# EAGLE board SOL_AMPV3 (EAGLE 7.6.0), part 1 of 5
S_REV: 1.2

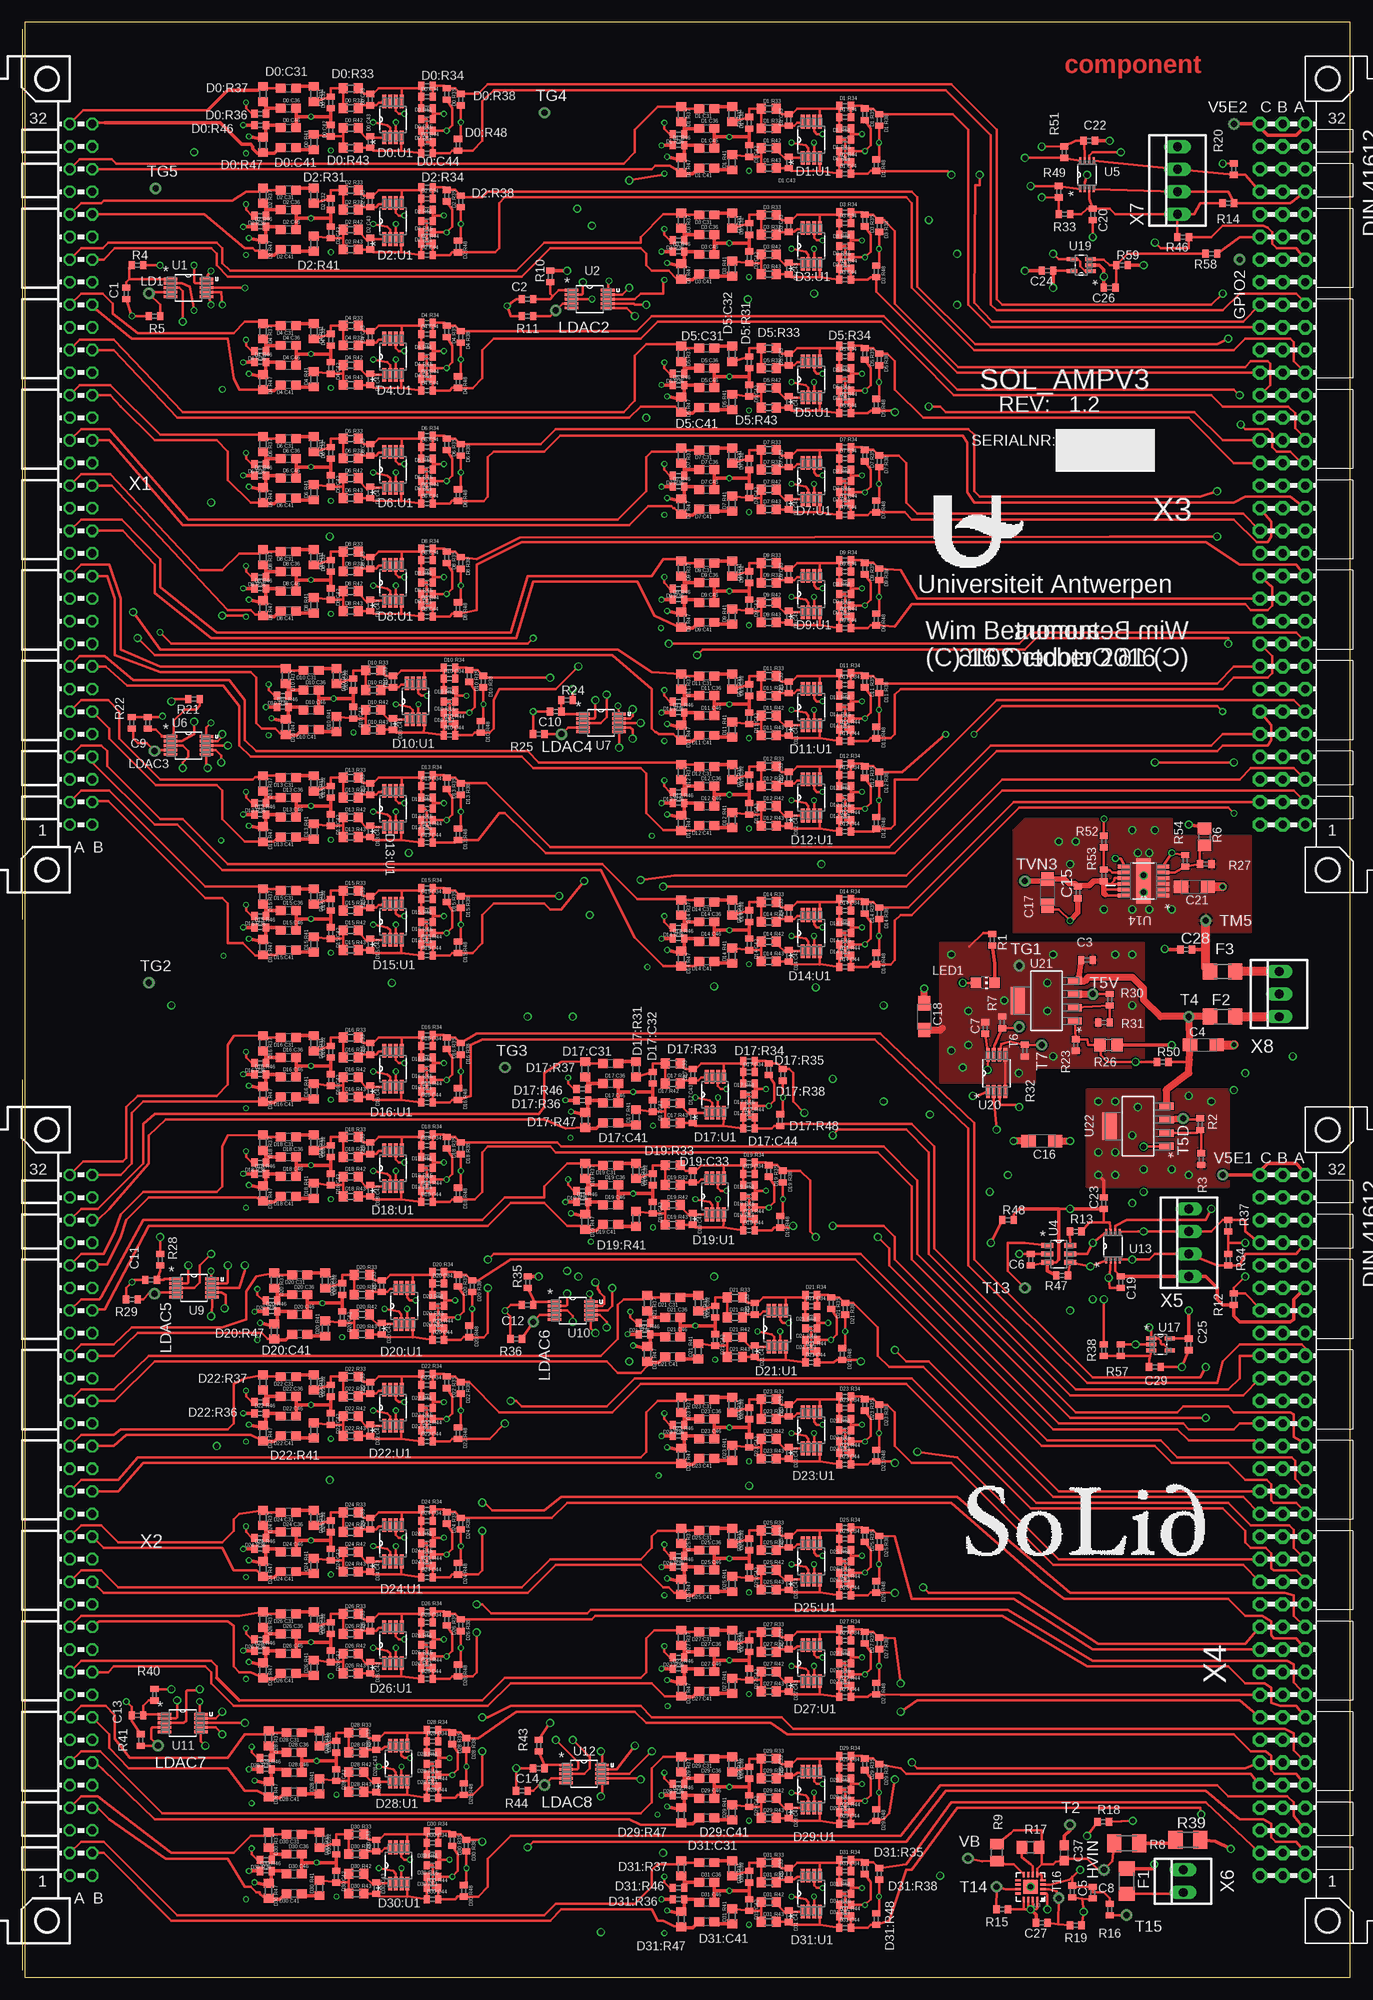
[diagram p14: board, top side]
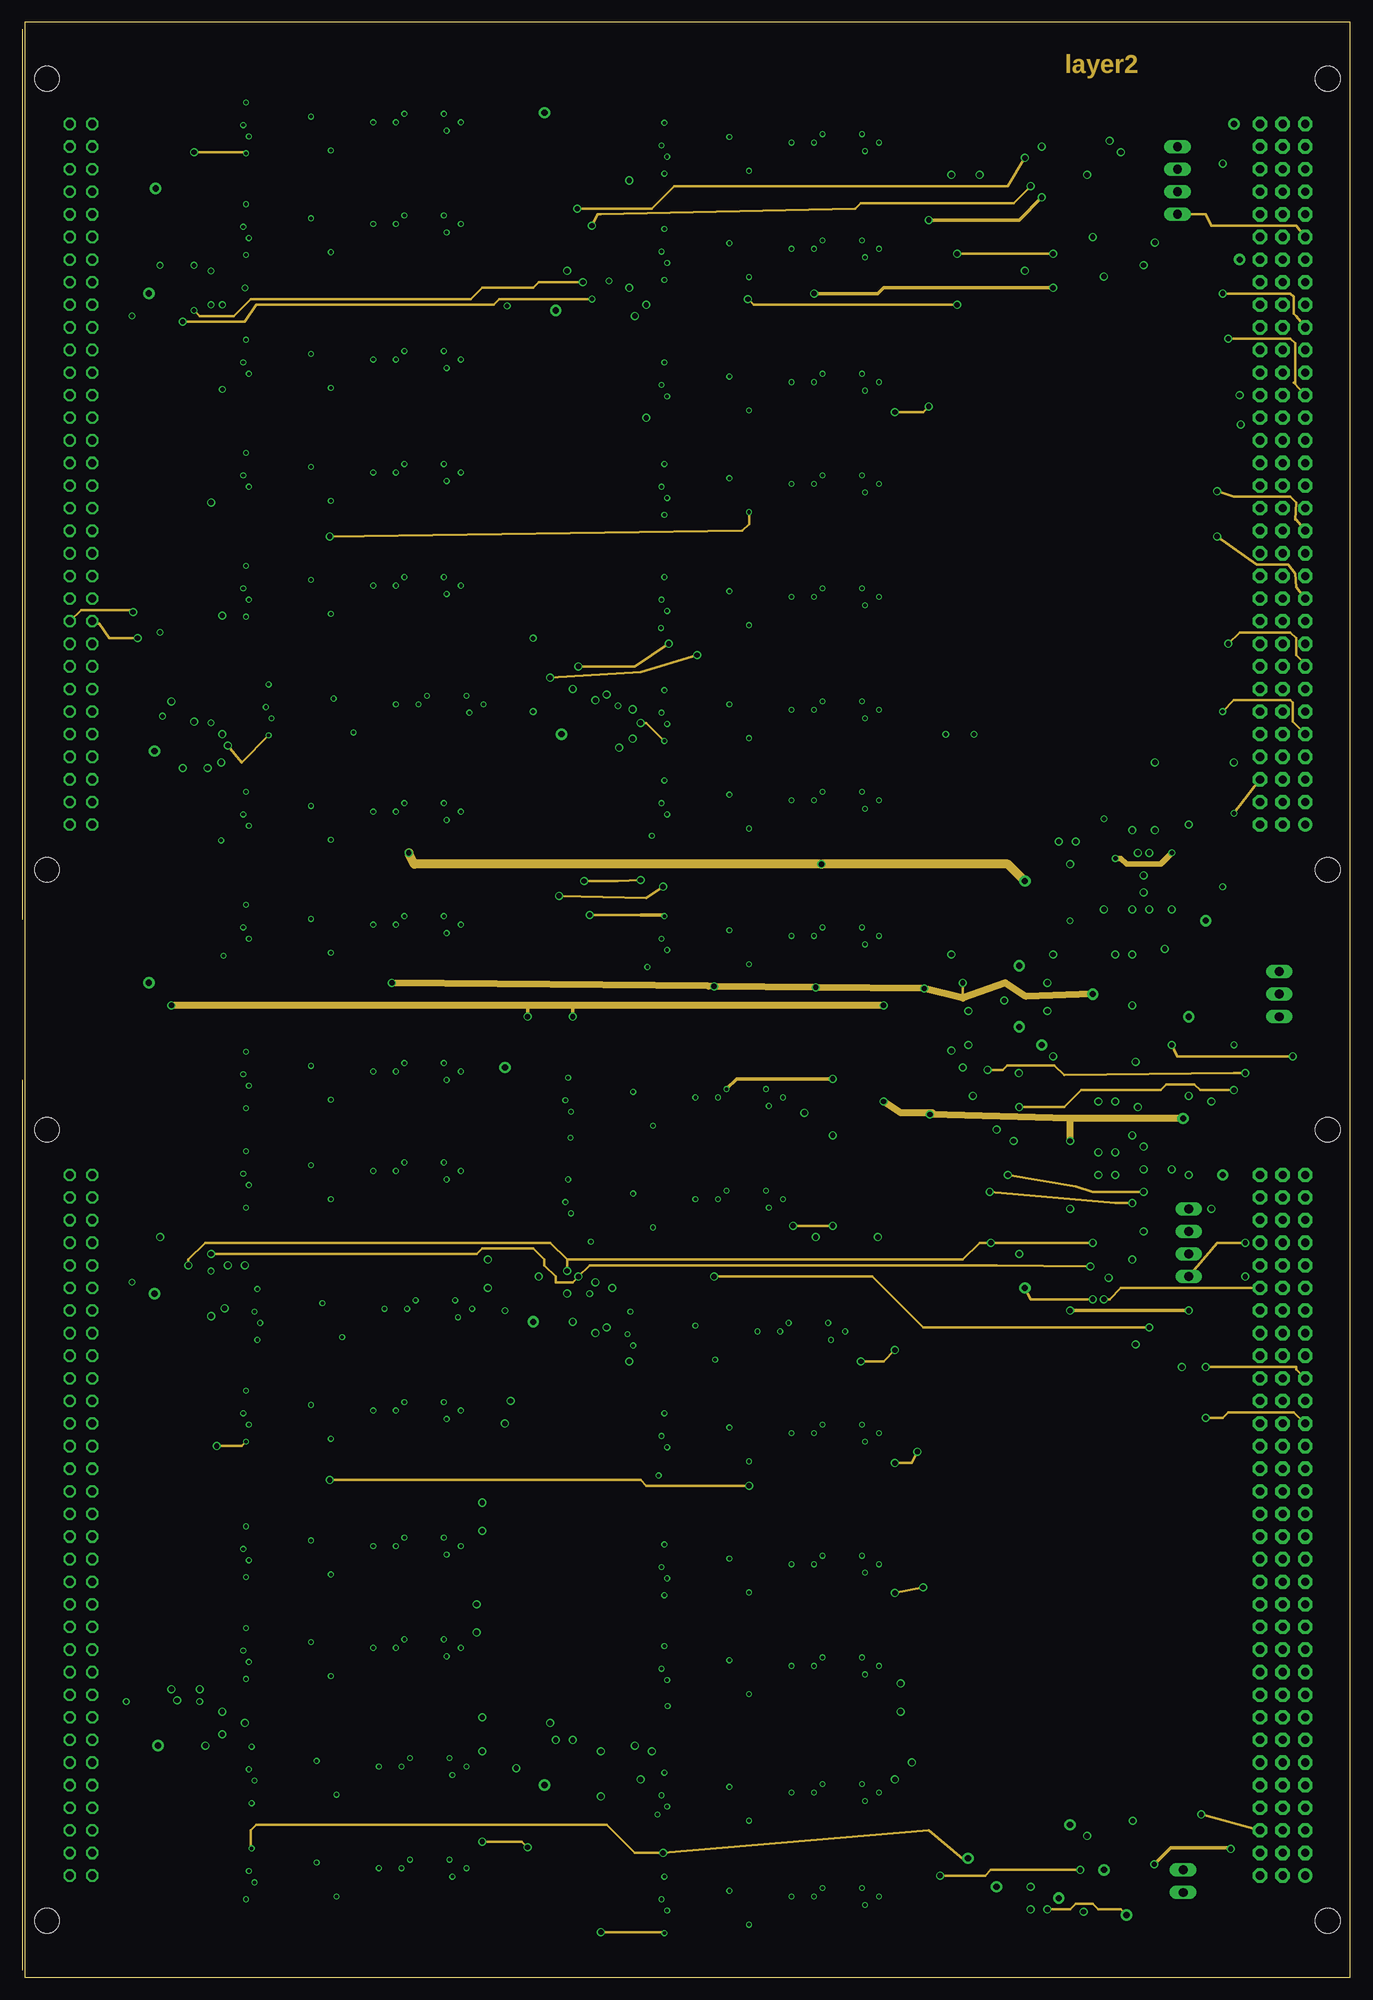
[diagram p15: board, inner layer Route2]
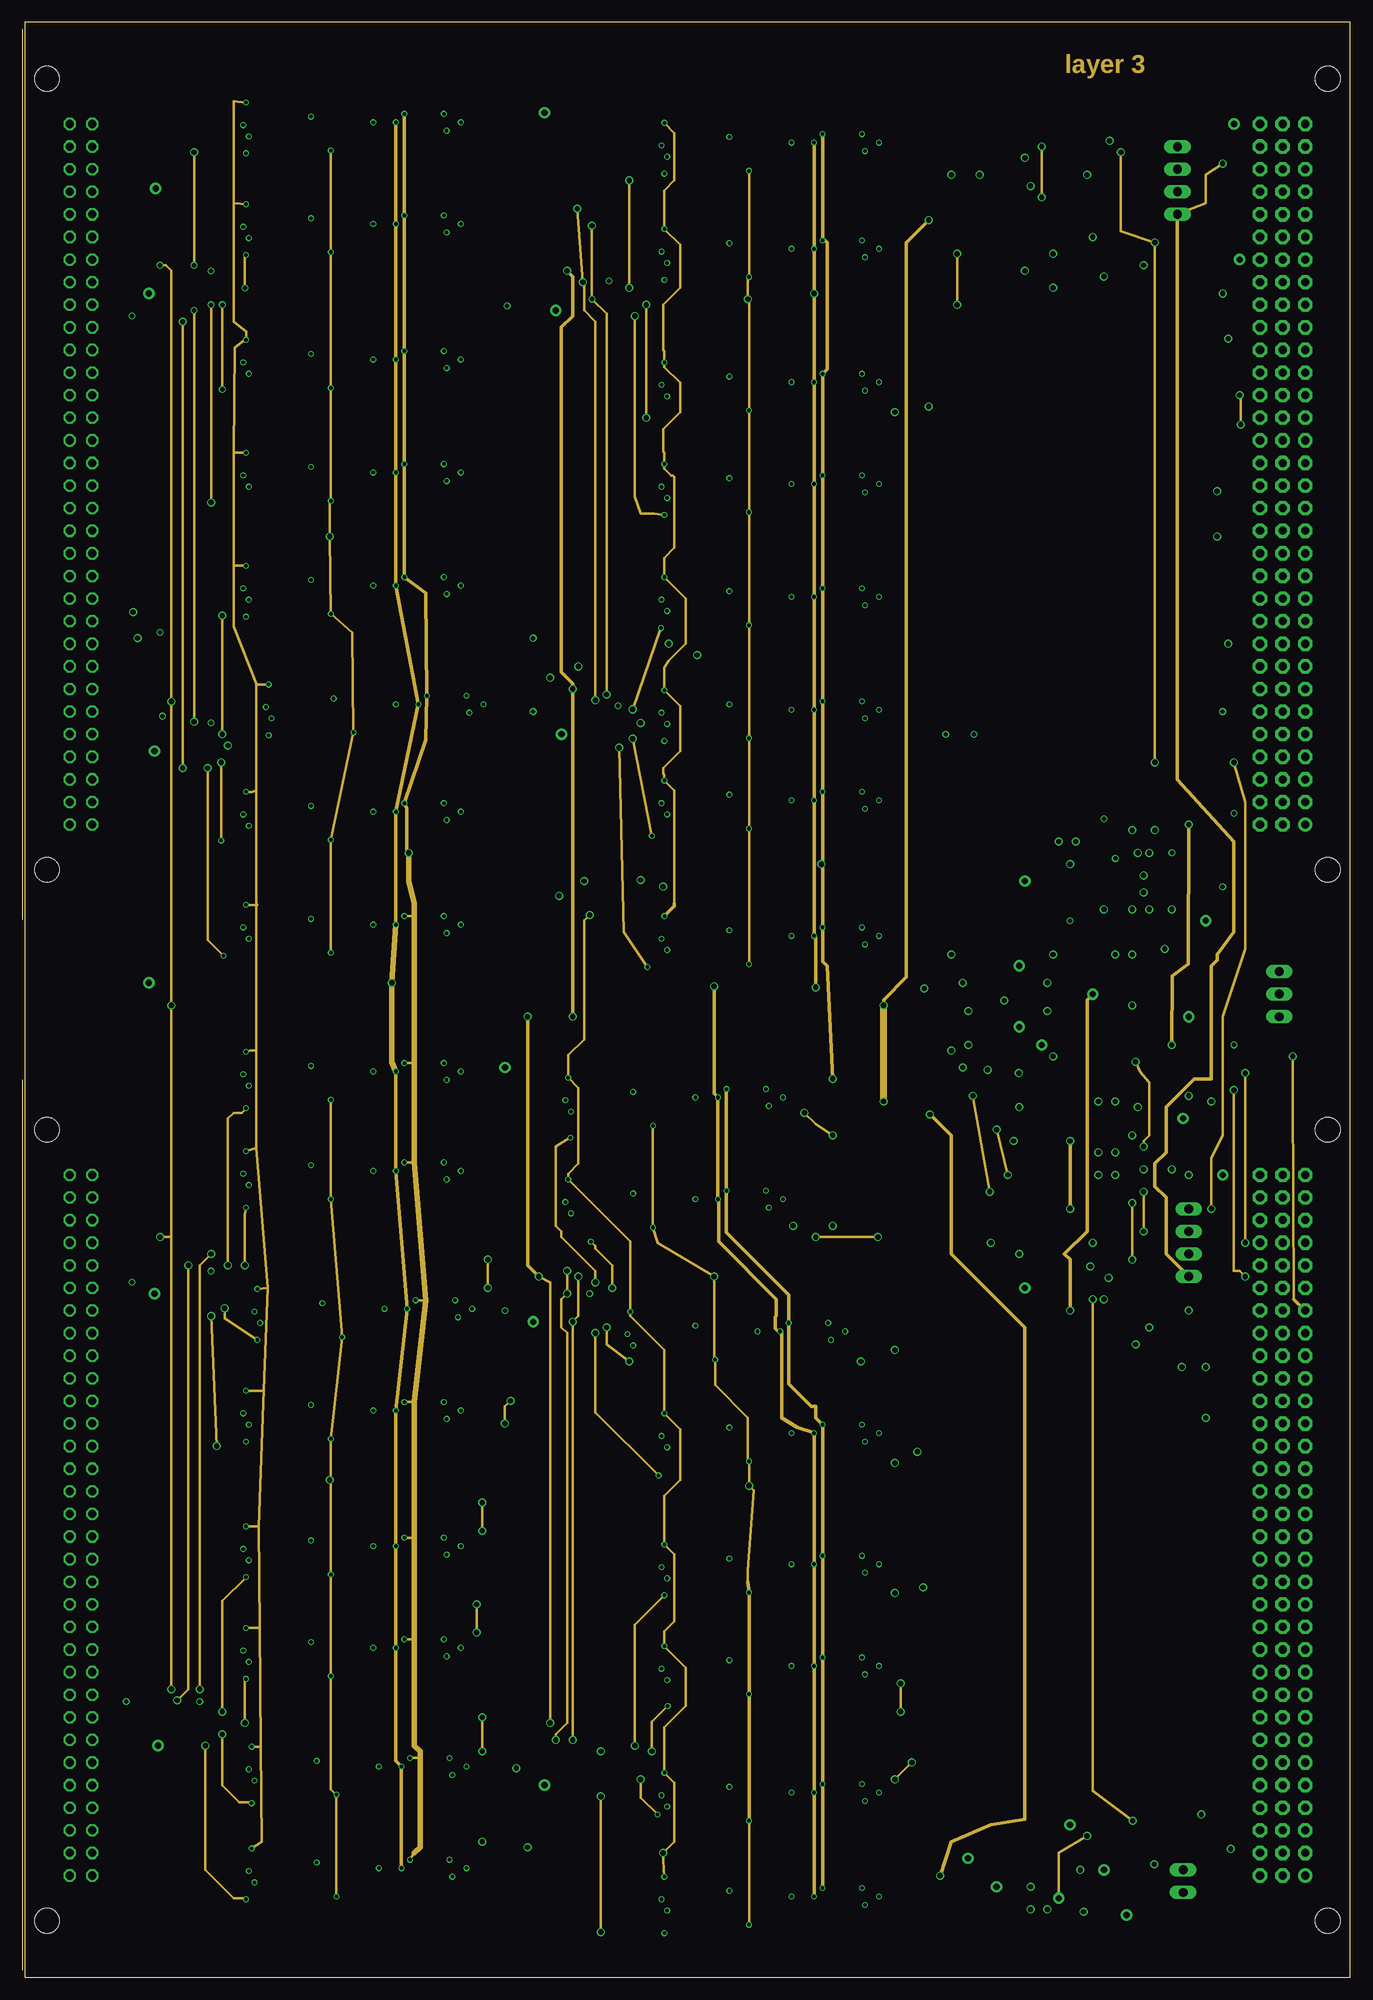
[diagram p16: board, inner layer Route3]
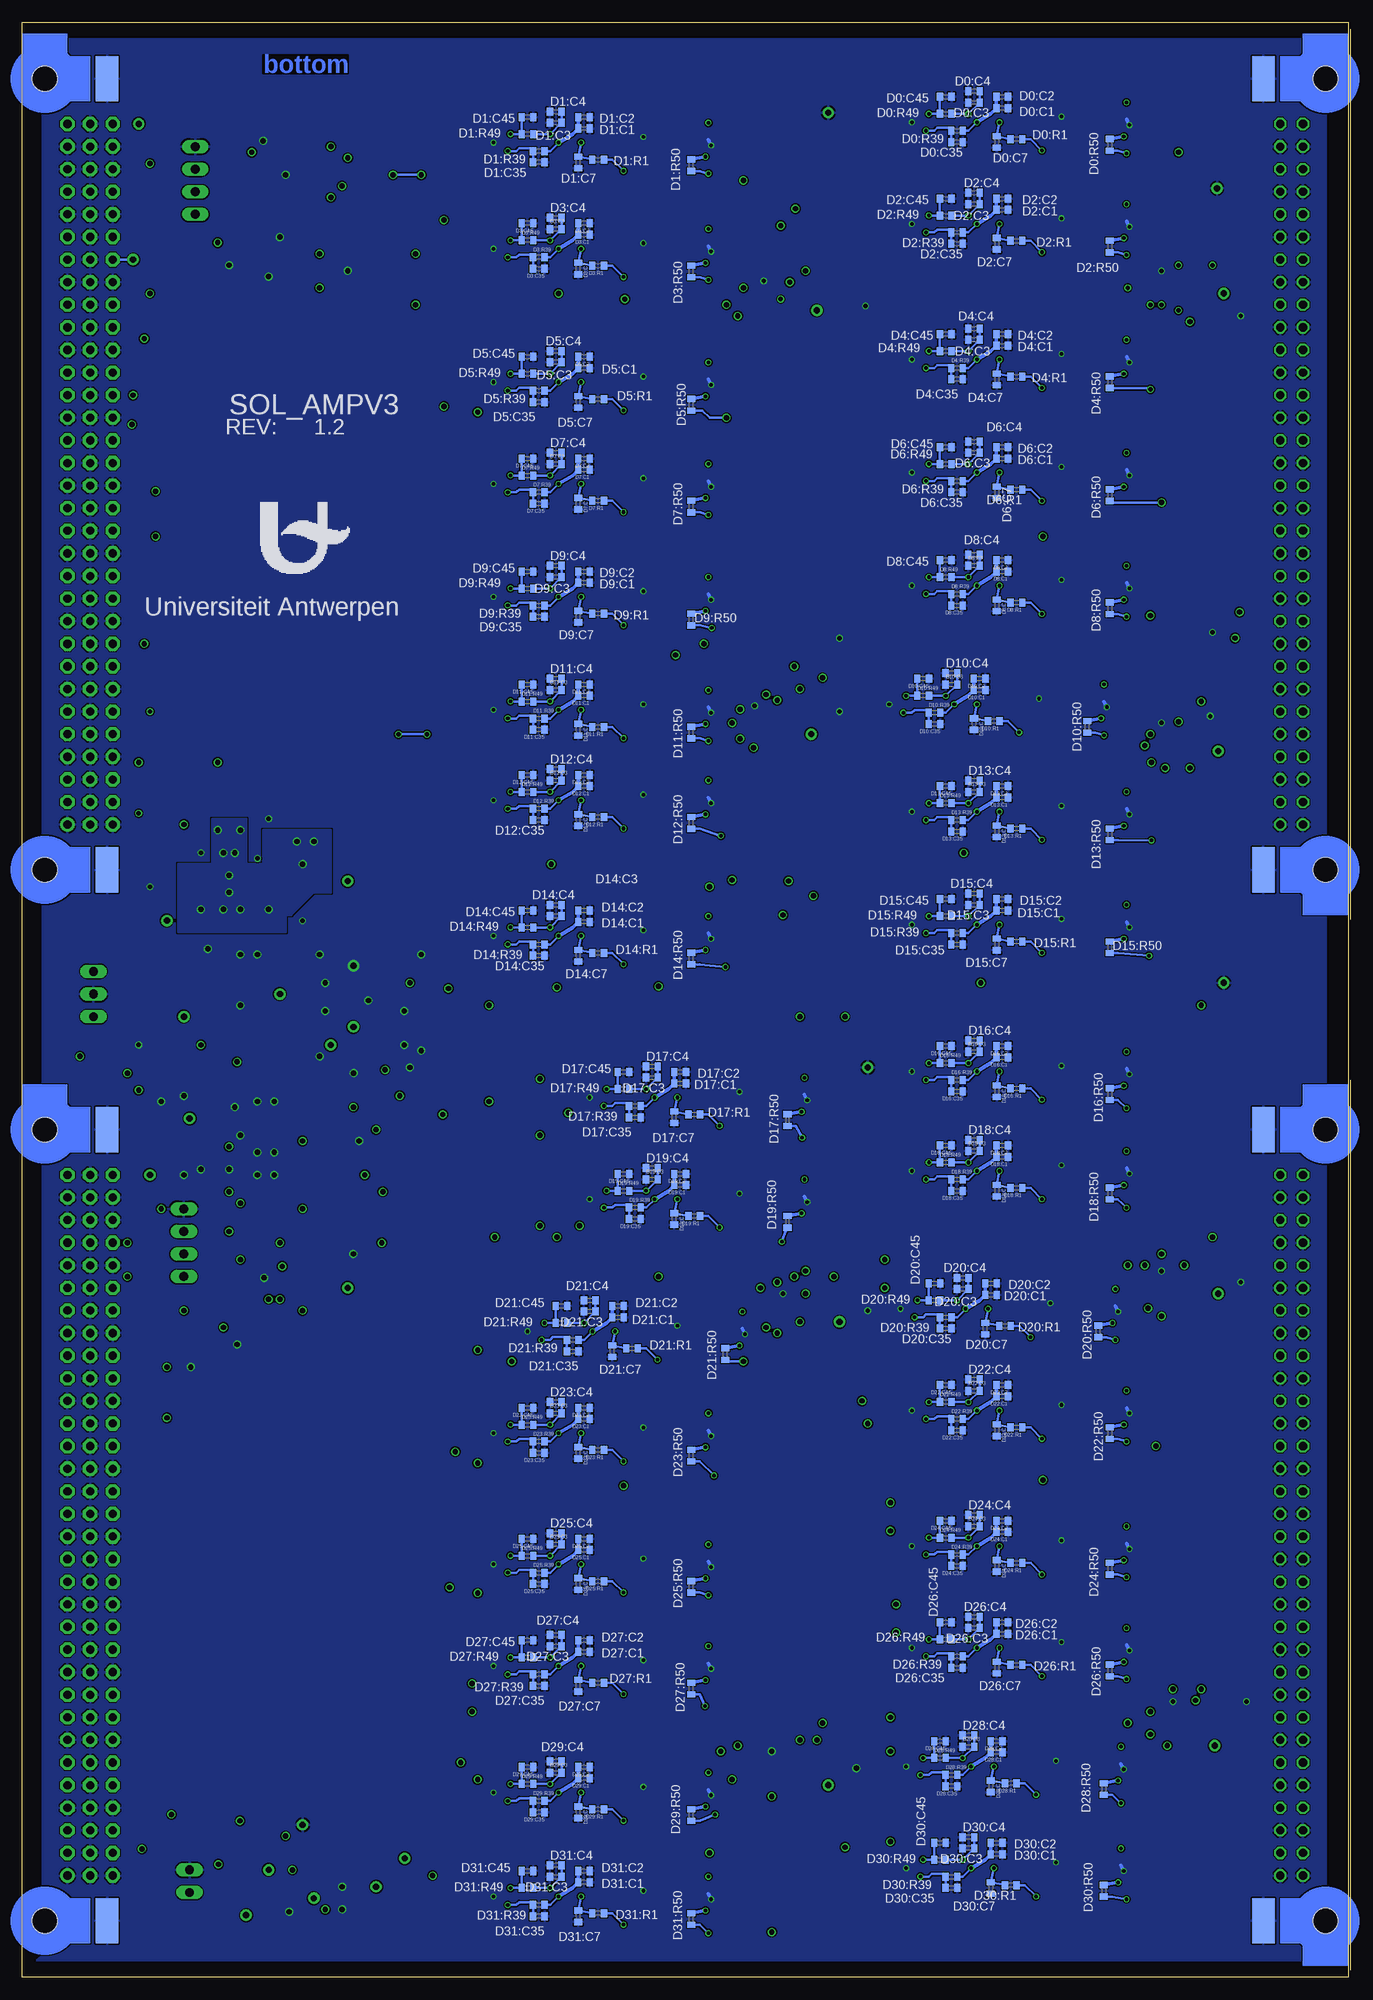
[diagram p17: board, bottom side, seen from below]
Size 149.22 x 219.71 mm. Coordinates in mm from the lower left corner, seen from the top.
Outline: 0.25,0 149.22,0 149.22,219.71 0.25,219.71 0.25,0
Copper layers (1+2*3+16): Top 0.018mm / dielectric 0.36mm / Route2 0.035mm / dielectric 0.71mm / Route3 0.035mm / dielectric 0.36mm / BOTTOM 0.018mm
Design rules "eC_4Layer_PClass6_BaseCopperO18-I35_eCDefault": minimum track width 0.15mm, minimum drill 0.35mm, track to track 0.15mm, track to pad 0.15mm, pad to pad 0.15mm, via to via 0.15mm, smd to smd 0mil, copper to edge 0.25mm, drill to drill 0.35mm, minimum pad ring 0.175mm, minimum via ring 0.125mm, stop-mask expansion 0mil, vias tented up to drill 0.45mm, thermal gap 0.2mm

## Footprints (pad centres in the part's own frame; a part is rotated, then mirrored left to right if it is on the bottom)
C0402 = smd 0.7 x 0.9: 1 -0.65,0; 2 0.65,0
SMC_A = smd 1.6 x 1.4: + -1.5,0; - 1.5,0
C0603 = smd 1.1 x 1: 1 -0.85,0; 2 0.85,0
R0402 = smd 0.7 x 0.9: 1 -0.65,0; 2 0.65,0
R0603 = smd 1 x 1.1: 1 -0.85,0; 2 0.85,0
SOP65P490X110-8N = smd 1.524 x 0.457: 1 -2.032,0.965; 2 -2.032,0.33; 3 -2.032,-0.33; 4 -2.032,-0.965; 5 2.032,-0.965; 6 2.032,-0.33; 7 2.032,0.33; 8 2.032,0.965
FUSE1206 = smd 1.6 x 1.803: 1 -1.422,0; 2 1.422,0
UA_P1-13 = drill 0.7 pad 1.27: TP 0,0
CHIP-LED0805 = smd 1.2 x 1.2: A 0,-1.05; C 0,1.05
R0805 = smd 1.3 x 1.5: 1 -0.95,0; 2 0.95,0
M1206 = smd 1.6 x 2: 1 -1.4,0; 2 1.4,0
R0805H = smd 1.143 x 1.5: 1 -0.95,0; 2 0.95,0
SOP50P490X110-10N = smd 1.524 x 0.33: 1 -2.032,0.991; 2 -2.032,0.508; 3 -2.032,0; 4 -2.032,-0.508; 5 -2.032,-0.991; 6 2.032,-0.991; 7 2.032,-0.508; 8 2.032,0; 9 2.032,0.508; 10 2.032,0.991
LFCSP_LQ-16_MANSOL = smd 0.61 x 0.25: 1 -1.405,0.75; 2 -1.405,0.25; 3 -1.405,-0.25; 4 -1.405,-0.75; 9 1.405,-0.75; 10 1.405,-0.25; 11 1.405,0.25; 12 1.405,0.75 | smd 0.25 x 0.61: 5 -0.75,-1.405; 6 -0.25,-1.405; 7 0.25,-1.405; 8 0.75,-1.405; 13 0.75,1.405; 14 0.25,1.405; 15 -0.25,1.405; 16 -0.75,1.405 | smd 1.6 x 1.6: EXP 0,0
SOT95P270X145-6N = smd 1.321 x 0.559: 1 -1.295,0.94; 2 -1.295,0; 3 -1.295,-0.94; 4 1.295,-0.94; 5 1.295,0; 6 1.295,0.94
SOP50P310X90-8N = smd 0.711 x 0.254: 1 -1.6,0.762; 2 -1.6,0.254; 3 -1.6,-0.254; 4 -1.6,-0.762; 5 1.6,-0.762; 6 1.6,-0.254; 7 1.6,0.254; 8 1.6,0.762
SOP65P490X110H-13N = smd 1.397 x 0.432: 1 -2.184,1.626; 2 -2.184,0.965; 3 -2.184,0.33; 4 -2.184,-0.33; 5 -2.184,-0.965; 6 -2.184,-1.626; 7 2.184,-1.626; 8 2.184,-0.965; 9 2.184,-0.33; 10 2.184,0.33; 11 2.184,0.965; 12 2.184,1.626 | smd 1.651 x 5.08: 13 0,0
SOT65P240X110-5N = smd 1.168 x 0.457: 1 -1.041,0.66; 2 -1.041,0; 3 -1.041,-0.66; 4 1.041,-0.66; 5 1.041,0.66
SOP65P490X110-8N' = smd 1.499 x 0.432: 1 -2.057,0.965; 2 -2.057,0.33; 3 -2.057,-0.33; 4 -2.057,-0.965; 5 2.057,-0.965; 6 2.057,-0.33; 7 2.057,0.33; 8 2.057,0.965
SOT150P696X180-5N = smd 1.6 x 0.838: 1 -3.2,2.261; 2 -3.2,0.762; 3 -3.2,-0.762; 4 -3.2,-2.261 | smd 1.6 x 3.099: 5 3.2,0
MAB64 = drill 0.914 octagon: A1 -2.54,39.37; A2 -2.54,36.83; A3 -2.54,34.29; A4 -2.54,31.75; A5 -2.54,29.21; A6 -2.54,26.67; A7 -2.54,24.13; A8 -2.54,21.59; A9 -2.54,19.05; A10 -2.54,16.51; A11 -2.54,13.97; A12 -2.54,11.43; A13 -2.54,8.89; A14 -2.54,6.35; A15 -2.54,3.81; A16 -2.54,1.27; A17 -2.54,-1.27; A18 -2.54,-3.81; A19 -2.54,-6.35; A20 -2.54,-8.89; A21 -2.54,-11.43; A22 -2.54,-13.97; A23 -2.54,-16.51; A24 -2.54,-19.05; A25 -2.54,-21.59; A26 -2.54,-24.13; A27 -2.54,-26.67; A28 -2.54,-29.21; A29 -2.54,-31.75; A30 -2.54,-34.29; A31 -2.54,-36.83; A32 -2.54,-39.37; B1 -5.08,39.37; B2 -5.08,36.83; B3 -5.08,34.29; B4 -5.08,31.75; B5 -5.08,29.21; B6 -5.08,26.67; B7 -5.08,24.13; B8 -5.08,21.59; B9 -5.08,19.05; B10 -5.08,16.51; B11 -5.08,13.97; B12 -5.08,11.43; B13 -5.08,8.89; B14 -5.08,6.35; B15 -5.08,3.81; B16 -5.08,1.27; B17 -5.08,-1.27; B18 -5.08,-3.81; B19 -5.08,-6.35; B20 -5.08,-8.89; B21 -5.08,-11.43; B22 -5.08,-13.97; B23 -5.08,-16.51; B24 -5.08,-19.05; B25 -5.08,-21.59; B26 -5.08,-24.13; B27 -5.08,-26.67; B28 -5.08,-29.21; B29 -5.08,-31.75; B30 -5.08,-34.29; B31 -5.08,-36.83; B32 -5.08,-39.37 | smd 2.54 x 5.08 bottom: P$2 -6.985,-44.45; P$3 -6.985,44.45 | hole 2.794: 0,44.45; 0,-44.45
DIN41612_96RC = drill 0.914 pad 1.6: A1 2.54,-39.37 | drill 0.914 pad 1.6 octagon: A2 2.54,-36.83; A3 2.54,-34.29; A4 2.54,-31.75; A5 2.54,-29.21; A6 2.54,-26.67; A7 2.54,-24.13; A8 2.54,-21.59; A9 2.54,-19.05; A10 2.54,-16.51; A11 2.54,-13.97; A12 2.54,-11.43; A13 2.54,-8.89; A14 2.54,-6.35; A15 2.54,-3.81; A16 2.54,-1.27; A17 2.54,1.27; A18 2.54,3.81; A19 2.54,6.35; A20 2.54,8.89; A21 2.54,11.43; A22 2.54,13.97; A23 2.54,16.51; A24 2.54,19.05; A25 2.54,21.59; A26 2.54,24.13; A27 2.54,26.67; A28 2.54,29.21; A29 2.54,31.75; A30 2.54,34.29; A31 2.54,36.83; A32 2.54,39.37; B1 0,-39.37; B2 0,-36.83; B3 0,-34.29; B4 0,-31.75; B5 0,-29.21; B6 0,-26.67; B7 0,-24.13; B8 0,-21.59; B9 0,-19.05; B10 0,-16.51; B11 0,-13.97; B12 0,-11.43; B13 0,-8.89; B14 0,-6.35; B15 0,-3.81; B16 0,-1.27; B17 0,1.27; B18 0,3.81; B19 0,6.35; B20 0,8.89; B21 0,11.43; B22 0,13.97; B23 0,16.51; B24 0,19.05; B25 0,21.59; B26 0,24.13; B27 0,26.67; B28 0,29.21; B29 0,31.75; B30 0,34.29; B31 0,36.83; B32 0,39.37; C1 -2.54,-39.37; C2 -2.54,-36.83; C3 -2.54,-34.29; C4 -2.54,-31.75; C5 -2.54,-29.21; C6 -2.54,-26.67; C7 -2.54,-24.13; C8 -2.54,-21.59; C9 -2.54,-19.05; C10 -2.54,-16.51; C11 -2.54,-13.97; C12 -2.54,-11.43; C13 -2.54,-8.89; C14 -2.54,-6.35; C15 -2.54,-3.81; C16 -2.54,-1.27; C17 -2.54,1.27; C18 -2.54,3.81; C19 -2.54,6.35; C20 -2.54,8.89; C21 -2.54,11.43; C22 -2.54,13.97; C23 -2.54,16.51; C24 -2.54,19.05; C25 -2.54,21.59; C26 -2.54,24.13; C27 -2.54,26.67; C28 -2.54,29.21; C29 -2.54,31.75; C30 -2.54,34.29; C31 -2.54,36.83; C32 -2.54,39.37 | smd 2.54 x 5.08 bottom: P$1 -1.905,44.45; P$2 -1.905,-44.45 | hole 2.794: 5.08,44.45; 5.08,-44.45
22-23-2041 = drill 1 long: 1 -3.81,0; 2 -1.27,0; 3 1.27,0; 4 3.81,0
22-23-2021 = drill 1 long: 1 -1.27,0; 2 1.27,0
22-23-2031 = drill 1 long: 1 -2.54,0; 2 0,0; 3 2.54,0

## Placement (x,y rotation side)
C1  100n  [C0402]  11.68,189.23 270 top
C2  100n  [C0402]  56.77,188.59 180 top
C3  100n  [C0402]  119.63,114.3 180 top
C4  10u  [SMC_A]  132.72,104.78 0 top
C5  10n  [C0402]  117.98,9.65 270 top
C6  100n  [C0402]  113.28,80.64 90 top
C7  100n  [C0402]  108.2,106.68 90 top
C8  100n  [C0402]  120.27,9.53 270 top
C9  100n  [C0402]  14.1,140.97 90 top
C10  100n  [C0402]  59.94,142.24 180 top
C11  100n  [C0402]  14.48,78.36 180 top
C12  100n  [C0402]  56.77,75.56 180 top
C13  100n  [C0402]  12.95,29.46 180 top
C14  100n  [C0402]  58.04,23.5 180 top
C15  100n  [C0402]  118.62,121.92 90 top
C16  nc  [SMC_A]  114.55,93.98 180 top
C17  10u  [SMC_A]  115.19,121.92 90 top
C18  10u  [SMC_A]  101.35,107.95 270 top
C19  100n  [C0402]  123.44,78.11 270 top
C20  100n  [C0402]  120.27,198.12 270 top
C21  10u  [SMC_A]  131.7,122.56 180 top
C22  100n  [C0402]  119.89,206.38 0 top
C23  100n  [C0402]  121.54,87 90 top
C24  100n  [C0402]  115.19,191.77 180 top
C25  100n  [C0402]  131.06,71.12 270 top
C26  100n  [C0402]  122.17,189.87 180 top
C27  10n  [C0402]  114.55,6.1 180 top
C28  100n  [C0402]  130.78,115.49 0 top
C29  100n  [C0402]  127.25,68.58 0 top
C37  100n  [C0603]  117.09,13.97 90 top
D0:C1  100n  [C0402]  39.12,210.06 180 bottom
D0:C2  10n  [C0402]  39.12,211.33 180 bottom
D0:C3  100n  [C0402]  42.29,210.69 0 bottom
D0:C4  10n  [C0402]  42.29,211.96 0 bottom
D0:C7  10n  [C0402]  39.75,206.25 270 bottom
D0:C31  4.7n  [C0603]  29.91,212.28 180 top
D0:C32  150p  [C0402]  34.67,210.69 90 top
D0:C33  27p  [C0402]  39.12,211.01 90 top
D0:C34  nc  [C0402]  45.47,211.33 0 top
D0:C35  10n  [C0402]  44.2,206.25 180 bottom
D0:C36  100n  [C0603]  29.91,210.06 0 top
D0:C41  4.7n  [C0603]  29.91,205.61 180 top
D0:C42  150p  [C0402]  34.67,207.52 270 top
D0:C43  27p  [C0402]  39.12,206.25 270 top
D0:C44  nc  [C0402]  45.47,204.98 0 top
D0:C45  10n  [C0402]  45.47,211.33 180 bottom
D0:C46  100n  [C0603]  29.91,207.84 0 top
D0:R1  1K  [R0402]  37.53,206.57 180 bottom
D0:R31  24.3E  [R0603]  32.77,211.65 270 top
D0:R32  24.3E  [R0603]  36.89,210.06 0 top
D0:R33  2K7  [R0603]  36.89,212.28 0 top
D0:R34  200E  [R0402]  45.47,212.6 0 top
D0:R35  1K4  [R0402]  47.69,211.65 270 top
D0:R36  10K  [R0402]  26.73,209.42 180 top
D0:R37  100K  [R0603]  27.05,211.65 270 top
D0:R38  NC  [R0402]  49.28,211.01 270 top
D0:R39  10E  [R0402]  44.2,207.52 0 bottom
D0:R41  24.3E  [R0603]  32.77,206.25 90 top
D0:R42  24.3E  [R0603]  36.89,207.84 0 top
D0:R43  2K7  [R0603]  36.89,205.61 0 top
D0:R44  200E  [R0402]  45.47,206.25 0 top
D0:R45  1K5  [R0402]  45.47,208.79 180 top
D0:R46  10K  [R0402]  26.73,208.15 0 top
D0:R47  100K  [R0603]  27.05,205.93 270 top
D0:R48  20K  [R0402]  48.96,205.93 270 top
D0:R49  10E  [R0402]  45.47,209.42 0 bottom
D0:R50  470E  [R0402]  27.05,205.93 90 bottom
D0:R51  nc  [R0402]  45.47,210.06 180 top
D0:R61  nc  [R0402]  45.47,207.52 180 top
D0:U1  AD8132ARZMSOP  [SOP65P490X110-8N]  41.66,208.79 90 top
D1:C1  100n  [C0402]  86.11,207.77 180 bottom
D1:C2  10n  [C0402]  86.11,209.04 180 bottom
D1:C3  100n  [C0402]  89.28,208.41 0 bottom
D1:C4  10n  [C0402]  89.28,209.68 0 bottom
D1:C7  10n  [C0402]  86.74,203.96 270 bottom
D1:C31  4.7n  [C0603]  76.9,209.99 180 top
D1:C32  150p  [C0402]  81.66,208.41 90 top
D1:C33  27p  [C0402]  86.11,208.72 90 top
D1:C34  nc  [C0402]  92.46,209.04 0 top
D1:C35  10n  [C0402]  91.19,203.96 180 bottom
D1:C36  100n  [C0603]  76.9,207.77 0 top
D1:C41  4.7n  [C0603]  76.9,203.33 180 top
D1:C42  150p  [C0402]  81.66,205.23 270 top
D1:C43  27p  [C0402]  86.11,203.96 270 top
D1:C44  nc  [C0402]  92.46,202.69 0 top
D1:C45  10n  [C0402]  92.46,209.04 180 bottom
D1:C46  100n  [C0603]  76.9,205.55 0 top
D1:R1  1K  [R0402]  84.52,204.28 180 bottom
D1:R31  24.3E  [R0603]  79.76,209.36 270 top
D1:R32  24.3E  [R0603]  83.88,207.77 0 top
D1:R33  2K7  [R0603]  83.88,209.99 0 top
D1:R34  200E  [R0402]  92.46,210.31 0 top
D1:R35  1K4  [R0402]  94.68,209.36 270 top
D1:R36  10K  [R0402]  73.72,207.14 180 top
D1:R37  100K  [R0603]  74.04,209.36 270 top
D1:R38  NC  [R0402]  96.27,208.72 270 top
D1:R39  10E  [R0402]  91.19,205.23 0 bottom
D1:R41  24.3E  [R0603]  79.76,203.96 90 top
D1:R42  24.3E  [R0603]  83.88,205.55 0 top
D1:R43  2K7  [R0603]  83.88,203.33 0 top
D1:R44  200E  [R0402]  92.46,203.96 0 top
D1:R45  1K5  [R0402]  92.46,206.5 180 top
D1:R46  10K  [R0402]  73.72,205.87 0 top
D1:R47  100K  [R0603]  74.04,203.64 270 top
D1:R48  20K  [R0402]  95.95,203.64 270 top
D1:R49  10E  [R0402]  92.46,207.14 0 bottom
D1:R50  470E  [R0402]  74.04,203.64 90 bottom
D1:R51  nc  [R0402]  92.46,207.77 180 top
D1:R61  nc  [R0402]  92.46,205.23 180 top
D1:U1  AD8132ARZMSOP  [SOP65P490X110-8N]  88.65,206.5 90 top
D2:C1  100n  [C0402]  39.12,198.63 180 bottom
D2:C2  10n  [C0402]  39.12,199.9 180 bottom
D2:C3  100n  [C0402]  42.29,199.26 0 bottom
D2:C4  10n  [C0402]  42.29,200.53 0 bottom
D2:C7  10n  [C0402]  39.75,194.82 270 bottom
D2:C31  4.7n  [C0603]  29.91,200.85 180 top
D2:C32  150p  [C0402]  34.67,199.26 90 top
D2:C33  27p  [C0402]  39.12,199.58 90 top
D2:C34  nc  [C0402]  45.47,199.9 0 top
D2:C35  10n  [C0402]  44.2,194.82 180 bottom
D2:C36  100n  [C0603]  29.91,198.63 0 top
D2:C41  4.7n  [C0603]  29.91,194.18 180 top
D2:C42  150p  [C0402]  34.67,196.09 270 top
D2:C43  27p  [C0402]  39.12,194.82 270 top
D2:C44  nc  [C0402]  45.47,193.55 0 top
D2:C45  10n  [C0402]  45.47,199.9 180 bottom
D2:C46  100n  [C0603]  29.91,196.41 0 top
D2:R1  1K  [R0402]  37.53,195.14 180 bottom
D2:R31  24.3E  [R0603]  32.77,200.22 270 top
D2:R32  24.3E  [R0603]  36.89,198.63 0 top
D2:R33  2K7  [R0603]  36.89,200.85 0 top
D2:R34  200E  [R0402]  45.47,201.17 0 top
D2:R35  1K4  [R0402]  47.69,200.22 270 top
D2:R36  10K  [R0402]  26.73,197.99 180 top
D2:R37  100K  [R0603]  27.05,200.22 270 top
D2:R38  NC  [R0402]  49.28,199.58 270 top
D2:R39  10E  [R0402]  44.2,196.09 0 bottom
D2:R41  24.3E  [R0603]  32.77,194.82 90 top
D2:R42  24.3E  [R0603]  36.89,196.41 0 top
D2:R43  2K7  [R0603]  36.89,194.18 0 top
D2:R44  200E  [R0402]  45.47,194.82 0 top
D2:R45  1K5  [R0402]  45.47,197.36 180 top
D2:R46  10K  [R0402]  26.73,196.72 0 top
D2:R47  100K  [R0603]  27.05,194.5 270 top
D2:R48  20K  [R0402]  48.96,194.5 270 top
D2:R49  10E  [R0402]  45.47,197.99 0 bottom
D2:R50  470E  [R0402]  27.05,194.5 90 bottom
D2:R51  nc  [R0402]  45.47,198.63 180 top
D2:R61  nc  [R0402]  45.47,196.09 180 top
D2:U1  AD8132ARZMSOP  [SOP65P490X110-8N]  41.66,197.36 90 top
D3:C1  100n  [C0402]  86.11,195.83 180 bottom
D3:C2  10n  [C0402]  86.11,197.1 180 bottom
D3:C3  100n  [C0402]  89.28,196.47 0 bottom
D3:C4  10n  [C0402]  89.28,197.74 0 bottom
D3:C7  10n  [C0402]  86.74,192.02 270 bottom
D3:C31  4.7n  [C0603]  76.9,198.06 180 top
D3:C32  150p  [C0402]  81.66,196.47 90 top
D3:C33  27p  [C0402]  86.11,196.79 90 top
D3:C34  nc  [C0402]  92.46,197.1 0 top
D3:C35  10n  [C0402]  91.19,192.02 180 bottom
D3:C36  100n  [C0603]  76.9,195.83 0 top
D3:C41  4.7n  [C0603]  76.9,191.39 180 top
D3:C42  150p  [C0402]  81.66,193.29 270 top
D3:C43  27p  [C0402]  86.11,192.02 270 top
D3:C44  nc  [C0402]  92.46,190.75 0 top
D3:C45  10n  [C0402]  92.46,197.1 180 bottom
D3:C46  100n  [C0603]  76.9,193.61 0 top
D3:R1  1K  [R0402]  84.52,192.34 180 bottom
D3:R31  24.3E  [R0603]  79.76,197.42 270 top
D3:R32  24.3E  [R0603]  83.88,195.83 0 top
D3:R33  2K7  [R0603]  83.88,198.06 0 top
D3:R34  200E  [R0402]  92.46,198.37 0 top
D3:R35  1K4  [R0402]  94.68,197.42 270 top
D3:R36  10K  [R0402]  73.72,195.2 180 top
D3:R37  100K  [R0603]  74.04,197.42 270 top
D3:R38  NC  [R0402]  96.27,196.79 270 top
D3:R39  10E  [R0402]  91.19,193.29 0 bottom
D3:R41  24.3E  [R0603]  79.76,192.02 90 top
D3:R42  24.3E  [R0603]  83.88,193.61 0 top
D3:R43  2K7  [R0603]  83.88,191.39 0 top
D3:R44  200E  [R0402]  92.46,192.02 0 top
D3:R45  1K5  [R0402]  92.46,194.56 180 top
D3:R46  10K  [R0402]  73.72,193.93 0 top
D3:R47  100K  [R0603]  74.04,191.71 270 top
D3:R48  20K  [R0402]  95.95,191.71 270 top
D3:R49  10E  [R0402]  92.46,195.2 0 bottom
D3:R50  470E  [R0402]  74.04,191.71 90 bottom
D3:R51  nc  [R0402]  92.46,195.83 180 top
D3:R61  nc  [R0402]  92.46,193.29 180 top
D3:U1  AD8132ARZMSOP  [SOP65P490X110-8N]  88.65,194.56 90 top
D4:C1  100n  [C0402]  39.12,183.39 180 bottom
D4:C2  10n  [C0402]  39.12,184.66 180 bottom
D4:C3  100n  [C0402]  42.29,184.02 0 bottom
D4:C4  10n  [C0402]  42.29,185.29 0 bottom
D4:C7  10n  [C0402]  39.75,179.58 270 bottom
D4:C31  4.7n  [C0603]  29.91,185.61 180 top
D4:C32  150p  [C0402]  34.67,184.02 90 top
D4:C33  27p  [C0402]  39.12,184.34 90 top
D4:C34  nc  [C0402]  45.47,184.66 0 top
D4:C35  10n  [C0402]  44.2,179.58 180 bottom
D4:C36  100n  [C0603]  29.91,183.39 0 top
D4:C41  4.7n  [C0603]  29.91,178.94 180 top
D4:C42  150p  [C0402]  34.67,180.85 270 top
D4:C43  27p  [C0402]  39.12,179.58 270 top
D4:C44  nc  [C0402]  45.47,178.31 0 top
D4:C45  10n  [C0402]  45.47,184.66 180 bottom
D4:C46  100n  [C0603]  29.91,181.17 0 top
D4:R1  1K  [R0402]  37.53,179.9 180 bottom
D4:R31  24.3E  [R0603]  32.77,184.98 270 top
D4:R32  24.3E  [R0603]  36.89,183.39 0 top
D4:R33  2K7  [R0603]  36.89,185.61 0 top
D4:R34  200E  [R0402]  45.47,185.93 0 top
D4:R35  1K4  [R0402]  47.69,184.98 270 top
D4:R36  10K  [R0402]  26.73,182.75 180 top
D4:R37  100K  [R0603]  27.05,184.98 270 top
D4:R38  NC  [R0402]  49.28,184.34 270 top
D4:R39  10E  [R0402]  44.2,180.85 0 bottom
D4:R41  24.3E  [R0603]  32.77,179.58 90 top
D4:R42  24.3E  [R0603]  36.89,181.17 0 top
D4:R43  2K7  [R0603]  36.89,178.94 0 top
D4:R44  200E  [R0402]  45.47,179.58 0 top
D4:R45  1K5  [R0402]  45.47,182.12 180 top
D4:R46  10K  [R0402]  26.73,181.48 0 top
D4:R47  100K  [R0603]  27.05,179.26 270 top
D4:R48  20K  [R0402]  48.96,179.26 270 top
D4:R49  10E  [R0402]  45.47,182.75 0 bottom
D4:R50  470E  [R0402]  27.05,179.26 90 bottom
D4:R51  nc  [R0402]  45.47,183.39 180 top
D4:R61  nc  [R0402]  45.47,180.85 180 top
D4:U1  AD8132ARZMSOP  [SOP65P490X110-8N]  41.66,182.12 90 top
D5:C1  100n  [C0402]  86.11,180.85 180 bottom
D5:C2  10n  [C0402]  86.11,182.12 180 bottom
D5:C3  100n  [C0402]  89.28,181.48 0 bottom
D5:C4  10n  [C0402]  89.28,182.75 0 bottom
D5:C7  10n  [C0402]  86.74,177.04 270 bottom
D5:C31  4.7n  [C0603]  76.9,183.07 180 top
D5:C32  150p  [C0402]  81.66,181.48 90 top
D5:C33  27p  [C0402]  86.11,181.8 90 top
D5:C34  nc  [C0402]  92.46,182.12 0 top
D5:C35  10n  [C0402]  91.19,177.04 180 bottom
D5:C36  100n  [C0603]  76.9,180.85 0 top
D5:C41  4.7n  [C0603]  76.9,176.4 180 top
D5:C42  150p  [C0402]  81.66,178.31 270 top
D5:C43  27p  [C0402]  86.11,177.04 270 top
D5:C44  nc  [C0402]  92.46,175.77 0 top
D5:C45  10n  [C0402]  92.46,182.12 180 bottom
D5:C46  100n  [C0603]  76.9,178.63 0 top
D5:R1  1K  [R0402]  84.52,177.36 180 bottom
D5:R31  24.3E  [R0603]  79.76,182.44 270 top
D5:R32  24.3E  [R0603]  83.88,180.85 0 top
D5:R33  2K7  [R0603]  83.88,183.07 0 top
D5:R34  200E  [R0402]  92.46,183.39 0 top
D5:R35  1K4  [R0402]  94.68,182.44 270 top
D5:R36  10K  [R0402]  73.72,180.21 180 top
D5:R37  100K  [R0603]  74.04,182.44 270 top
D5:R38  NC  [R0402]  96.27,181.8 270 top
D5:R39  10E  [R0402]  91.19,178.31 0 bottom
D5:R41  24.3E  [R0603]  79.76,177.04 90 top
D5:R42  24.3E  [R0603]  83.88,178.63 0 top
D5:R43  2K7  [R0603]  83.88,176.4 0 top
D5:R44  200E  [R0402]  92.46,177.04 0 top
D5:R45  1K5  [R0402]  92.46,179.58 180 top
D5:R46  10K  [R0402]  73.72,178.94 0 top
D5:R47  100K  [R0603]  74.04,176.72 270 top
D5:R48  20K  [R0402]  95.95,176.72 270 top
D5:R49  10E  [R0402]  92.46,180.21 0 bottom
D5:R50  470E  [R0402]  74.04,176.72 90 bottom
D5:R51  nc  [R0402]  92.46,180.85 180 top
D5:R61  nc  [R0402]  92.46,178.31 180 top
D5:U1  AD8132ARZMSOP  [SOP65P490X110-8N]  88.65,179.58 90 top
D6:C1  100n  [C0402]  39.12,170.69 180 bottom
D6:C2  10n  [C0402]  39.12,171.96 180 bottom
D6:C3  100n  [C0402]  42.29,171.32 0 bottom
D6:C4  10n  [C0402]  42.29,172.59 0 bottom
D6:C7  10n  [C0402]  39.75,166.88 270 bottom
D6:C31  4.7n  [C0603]  29.91,172.91 180 top
D6:C32  150p  [C0402]  34.67,171.32 90 top
D6:C33  27p  [C0402]  39.12,171.64 90 top
D6:C34  nc  [C0402]  45.47,171.96 0 top
D6:C35  10n  [C0402]  44.2,166.88 180 bottom
D6:C36  100n  [C0603]  29.91,170.69 0 top
D6:C41  4.7n  [C0603]  29.91,166.24 180 top
D6:C42  150p  [C0402]  34.67,168.15 270 top
D6:C43  27p  [C0402]  39.12,166.88 270 top
D6:C44  nc  [C0402]  45.47,165.61 0 top
D6:C45  10n  [C0402]  45.47,171.96 180 bottom
D6:C46  100n  [C0603]  29.91,168.47 0 top
D6:R1  1K  [R0402]  37.53,167.2 180 bottom
D6:R31  24.3E  [R0603]  32.77,172.28 270 top
D6:R32  24.3E  [R0603]  36.89,170.69 0 top
D6:R33  2K7  [R0603]  36.89,172.91 0 top
D6:R34  200E  [R0402]  45.47,173.23 0 top
D6:R35  1K4  [R0402]  47.69,172.28 270 top
D6:R36  10K  [R0402]  26.73,170.05 180 top
D6:R37  100K  [R0603]  27.05,172.28 270 top
D6:R38  NC  [R0402]  49.28,171.64 270 top
D6:R39  10E  [R0402]  44.2,168.15 0 bottom
D6:R41  24.3E  [R0603]  32.77,166.88 90 top
D6:R42  24.3E  [R0603]  36.89,168.47 0 top
D6:R43  2K7  [R0603]  36.89,166.24 0 top
D6:R44  200E  [R0402]  45.47,166.88 0 top
D6:R45  1K5  [R0402]  45.47,169.42 180 top
D6:R46  10K  [R0402]  26.73,168.78 0 top
D6:R47  100K  [R0603]  27.05,166.56 270 top
D6:R48  20K  [R0402]  48.96,166.56 270 top
D6:R49  10E  [R0402]  45.47,170.05 0 bottom
D6:R50  470E  [R0402]  27.05,166.56 90 bottom
D6:R51  nc  [R0402]  45.47,170.69 180 top
D6:R61  nc  [R0402]  45.47,168.15 180 top
D6:U1  AD8132ARZMSOP  [SOP65P490X110-8N]  41.66,169.42 90 top
D7:C1  100n  [C0402]  86.11,169.42 180 bottom
D7:C2  10n  [C0402]  86.11,170.69 180 bottom
D7:C3  100n  [C0402]  89.28,170.05 0 bottom
D7:C4  10n  [C0402]  89.28,171.32 0 bottom
D7:C7  10n  [C0402]  86.74,165.61 270 bottom
D7:C31  4.7n  [C0603]  76.9,171.64 180 top
D7:C32  150p  [C0402]  81.66,170.05 90 top
D7:C33  27p  [C0402]  86.11,170.37 90 top
D7:C34  nc  [C0402]  92.46,170.69 0 top
D7:C35  10n  [C0402]  91.19,165.61 180 bottom
D7:C36  100n  [C0603]  76.9,169.42 0 top
D7:C41  4.7n  [C0603]  76.9,164.97 180 top
D7:C42  150p  [C0402]  81.66,166.88 270 top
D7:C43  27p  [C0402]  86.11,165.61 270 top
D7:C44  nc  [C0402]  92.46,164.34 0 top
D7:C45  10n  [C0402]  92.46,170.69 180 bottom
D7:C46  100n  [C0603]  76.9,167.2 0 top
D7:R1  1K  [R0402]  84.52,165.93 180 bottom
D7:R31  24.3E  [R0603]  79.76,171.01 270 top
D7:R32  24.3E  [R0603]  83.88,169.42 0 top
D7:R33  2K7  [R0603]  83.88,171.64 0 top
D7:R34  200E  [R0402]  92.46,171.96 0 top
D7:R35  1K4  [R0402]  94.68,171.01 270 top
D7:R36  10K  [R0402]  73.72,168.78 180 top
D7:R37  100K  [R0603]  74.04,171.01 270 top
D7:R38  NC  [R0402]  96.27,170.37 270 top
D7:R39  10E  [R0402]  91.19,166.88 0 bottom
D7:R41  24.3E  [R0603]  79.76,165.61 90 top
D7:R42  24.3E  [R0603]  83.88,167.2 0 top
D7:R43  2K7  [R0603]  83.88,164.97 0 top
D7:R44  200E  [R0402]  92.46,165.61 0 top
D7:R45  1K5  [R0402]  92.46,168.15 180 top
D7:R46  10K  [R0402]  73.72,167.51 0 top
D7:R47  100K  [R0603]  74.04,165.29 270 top
D7:R48  20K  [R0402]  95.95,165.29 270 top
D7:R49  10E  [R0402]  92.46,168.78 0 bottom
D7:R50  470E  [R0402]  74.04,165.29 90 bottom
D7:R51  nc  [R0402]  92.46,169.42 180 top
D7:R61  nc  [R0402]  92.46,166.88 180 top
D7:U1  AD8132ARZMSOP  [SOP65P490X110-8N]  88.65,168.15 90 top
D8:C1  100n  [C0402]  39.12,157.99 180 bottom
D8:C2  10n  [C0402]  39.12,159.26 180 bottom
D8:C3  100n  [C0402]  42.29,158.62 0 bottom
D8:C4  10n  [C0402]  42.29,159.89 0 bottom
D8:C7  10n  [C0402]  39.75,154.18 270 bottom
D8:C31  4.7n  [C0603]  29.91,160.21 180 top
D8:C32  150p  [C0402]  34.67,158.62 90 top
D8:C33  27p  [C0402]  39.12,158.94 90 top
D8:C34  nc  [C0402]  45.47,159.26 0 top
D8:C35  10n  [C0402]  44.2,154.18 180 bottom
D8:C36  100n  [C0603]  29.91,157.99 0 top
D8:C41  4.7n  [C0603]  29.91,153.54 180 top
D8:C42  150p  [C0402]  34.67,155.45 270 top
D8:C43  27p  [C0402]  39.12,154.18 270 top
D8:C44  nc  [C0402]  45.47,152.91 0 top
D8:C45  10n  [C0402]  45.47,159.26 180 bottom
D8:C46  100n  [C0603]  29.91,155.77 0 top
D8:R1  1K  [R0402]  37.53,154.5 180 bottom
D8:R31  24.3E  [R0603]  32.77,159.58 270 top
D8:R32  24.3E  [R0603]  36.89,157.99 0 top
D8:R33  2K7  [R0603]  36.89,160.21 0 top
D8:R34  200E  [R0402]  45.47,160.53 0 top
D8:R35  1K4  [R0402]  47.69,159.58 270 top
D8:R36  10K  [R0402]  26.73,157.35 180 top
D8:R37  100K  [R0603]  27.05,159.58 270 top
D8:R38  NC  [R0402]  49.28,158.94 270 top
D8:R39  10E  [R0402]  44.2,155.45 0 bottom
D8:R41  24.3E  [R0603]  32.77,154.18 90 top
D8:R42  24.3E  [R0603]  36.89,155.77 0 top
D8:R43  2K7  [R0603]  36.89,153.54 0 top
D8:R44  200E  [R0402]  45.47,154.18 0 top
D8:R45  1K5  [R0402]  45.47,156.72 180 top
D8:R46  10K  [R0402]  26.73,156.08 0 top
D8:R47  100K  [R0603]  27.05,153.86 270 top
D8:R48  20K  [R0402]  48.96,153.86 270 top
D8:R49  10E  [R0402]  45.47,157.35 0 bottom
D8:R50  470E  [R0402]  27.05,153.86 90 bottom
D8:R51  nc  [R0402]  45.47,157.99 180 top
D8:R61  nc  [R0402]  45.47,155.45 180 top
D8:U1  AD8132ARZMSOP  [SOP65P490X110-8N]  41.66,156.72 90 top
D9:C1  100n  [C0402]  86.11,156.72 180 bottom
D9:C2  10n  [C0402]  86.11,157.99 180 bottom
D9:C3  100n  [C0402]  89.28,157.35 0 bottom
D9:C4  10n  [C0402]  89.28,158.62 0 bottom
D9:C7  10n  [C0402]  86.74,152.91 270 bottom
D9:C31  4.7n  [C0603]  76.9,158.94 180 top
D9:C32  150p  [C0402]  81.66,157.35 90 top
D9:C33  27p  [C0402]  86.11,157.67 90 top
D9:C34  nc  [C0402]  92.46,157.99 0 top
D9:C35  10n  [C0402]  91.19,152.91 180 bottom
D9:C36  100n  [C0603]  76.9,156.72 0 top
D9:C41  4.7n  [C0603]  76.9,152.27 180 top
D9:C42  150p  [C0402]  81.66,154.18 270 top
D9:C43  27p  [C0402]  86.11,152.91 270 top
D9:C44  nc  [C0402]  92.46,151.64 0 top
D9:C45  10n  [C0402]  92.46,157.99 180 bottom
D9:C46  100n  [C0603]  76.9,154.5 0 top
D9:R1  1K  [R0402]  84.52,153.23 180 bottom
D9:R31  24.3E  [R0603]  79.76,158.31 270 top
D9:R32  24.3E  [R0603]  83.88,156.72 0 top
D9:R33  2K7  [R0603]  83.88,158.94 0 top
D9:R34  200E  [R0402]  92.46,159.26 0 top
D9:R35  1K4  [R0402]  94.68,158.31 270 top
D9:R36  10K  [R0402]  73.72,156.08 180 top
D9:R37  100K  [R0603]  74.04,158.31 270 top
D9:R38  NC  [R0402]  96.27,157.67 270 top
D9:R39  10E  [R0402]  91.19,154.18 0 bottom
D9:R41  24.3E  [R0603]  79.76,152.91 90 top
D9:R42  24.3E  [R0603]  83.88,154.5 0 top
D9:R43  2K7  [R0603]  83.88,152.27 0 top
D9:R44  200E  [R0402]  92.46,152.91 0 top
D9:R45  1K5  [R0402]  92.46,155.45 180 top
D9:R46  10K  [R0402]  73.72,154.81 0 top
D9:R47  100K  [R0603]  74.04,152.59 270 top
D9:R48  20K  [R0402]  95.95,152.59 270 top
D9:R49  10E  [R0402]  92.46,156.08 0 bottom
D9:R50  470E  [R0402]  74.04,152.59 90 bottom
D9:R51  nc  [R0402]  92.46,156.72 180 top
D9:R61  nc  [R0402]  92.46,154.18 180 top
D9:U1  AD8132ARZMSOP  [SOP65P490X110-8N]  88.65,155.45 90 top
D10:C1  100n  [C0402]  41.66,144.65 180 bottom
D10:C2  10n  [C0402]  41.66,145.92 180 bottom
D10:C3  100n  [C0402]  44.83,145.29 0 bottom
D10:C4  10n  [C0402]  44.83,146.56 0 bottom
D10:C7  10n  [C0402]  42.29,140.84 270 bottom
D10:C31  4.7n  [C0603]  32.45,146.88 180 top
D10:C32  150p  [C0402]  37.21,145.29 90 top
D10:C33  27p  [C0402]  41.66,145.61 90 top
D10:C34  nc  [C0402]  48.01,145.92 0 top
D10:C35  10n  [C0402]  46.74,140.84 180 bottom
D10:C36  100n  [C0603]  32.45,144.65 0 top
D10:C41  4.7n  [C0603]  32.45,140.21 180 top
D10:C42  150p  [C0402]  37.21,142.11 270 top
D10:C43  27p  [C0402]  41.66,140.84 270 top
D10:C44  nc  [C0402]  48.01,139.57 0 top
D10:C45  10n  [C0402]  48.01,145.92 180 bottom
D10:C46  100n  [C0603]  32.45,142.43 0 top
D10:R1  1K  [R0402]  40.07,141.16 180 bottom
D10:R31  24.3E  [R0603]  35.31,146.24 270 top
D10:R32  24.3E  [R0603]  39.43,144.65 0 top
D10:R33  2K7  [R0603]  39.43,146.88 0 top
D10:R34  200E  [R0402]  48.01,147.19 0 top
D10:R35  1K4  [R0402]  50.23,146.24 270 top
D10:R36  10K  [R0402]  29.27,144.02 180 top
D10:R37  100K  [R0603]  29.59,146.24 270 top
D10:R38  NC  [R0402]  51.82,145.61 270 top
D10:R39  10E  [R0402]  46.74,142.11 0 bottom
D10:R41  24.3E  [R0603]  35.31,140.84 90 top
D10:R42  24.3E  [R0603]  39.43,142.43 0 top
D10:R43  2K7  [R0603]  39.43,140.21 0 top
D10:R44  200E  [R0402]  48.01,140.84 0 top
D10:R45  1K5  [R0402]  48.01,143.38 180 top
D10:R46  10K  [R0402]  29.27,142.75 0 top
D10:R47  100K  [R0603]  29.59,140.53 270 top
D10:R48  20K  [R0402]  51.5,140.53 270 top
D10:R49  10E  [R0402]  48.01,144.02 0 bottom
D10:R50  470E  [R0402]  29.59,140.53 90 bottom
D10:R51  nc  [R0402]  48.01,144.65 180 top
D10:R61  nc  [R0402]  48.01,142.11 180 top
D10:U1  AD8132ARZMSOP  [SOP65P490X110-8N]  44.2,143.38 90 top
D11:C1  100n  [C0402]  86.11,144.02 180 bottom
D11:C2  10n  [C0402]  86.11,145.29 180 bottom
D11:C3  100n  [C0402]  89.28,144.65 0 bottom
D11:C4  10n  [C0402]  89.28,145.92 0 bottom
D11:C7  10n  [C0402]  86.74,140.21 270 bottom
D11:C31  4.7n  [C0603]  76.9,146.24 180 top
D11:C32  150p  [C0402]  81.66,144.65 90 top
D11:C33  27p  [C0402]  86.11,144.97 90 top
D11:C34  nc  [C0402]  92.46,145.29 0 top
D11:C35  10n  [C0402]  91.19,140.21 180 bottom
D11:C36  100n  [C0603]  76.9,144.02 0 top
D11:C41  4.7n  [C0603]  76.9,139.57 180 top
D11:C42  150p  [C0402]  81.66,141.48 270 top
D11:C43  27p  [C0402]  86.11,140.21 270 top
D11:C44  nc  [C0402]  92.46,138.94 0 top
D11:C45  10n  [C0402]  92.46,145.29 180 bottom
D11:C46  100n  [C0603]  76.9,141.8 0 top
D11:R1  1K  [R0402]  84.52,140.53 180 bottom
D11:R31  24.3E  [R0603]  79.76,145.61 270 top
D11:R32  24.3E  [R0603]  83.88,144.02 0 top
D11:R33  2K7  [R0603]  83.88,146.24 0 top
D11:R34  200E  [R0402]  92.46,146.56 0 top
D11:R35  1K4  [R0402]  94.68,145.61 270 top
D11:R36  10K  [R0402]  73.72,143.38 180 top
D11:R37  100K  [R0603]  74.04,145.61 270 top
D11:R38  NC  [R0402]  96.27,144.97 270 top
D11:R39  10E  [R0402]  91.19,141.48 0 bottom
D11:R41  24.3E  [R0603]  79.76,140.21 90 top
D11:R42  24.3E  [R0603]  83.88,141.8 0 top
D11:R43  2K7  [R0603]  83.88,139.57 0 top
D11:R44  200E  [R0402]  92.46,140.21 0 top
D11:R45  1K5  [R0402]  92.46,142.75 180 top
D11:R46  10K  [R0402]  73.72,142.11 0 top
D11:R47  100K  [R0603]  74.04,139.89 270 top
D11:R48  20K  [R0402]  95.95,139.89 270 top
D11:R49  10E  [R0402]  92.46,143.38 0 bottom
D11:R50  470E  [R0402]  74.04,139.89 90 bottom
D11:R51  nc  [R0402]  92.46,144.02 180 top
D11:R61  nc  [R0402]  92.46,141.48 180 top
D11:U1  AD8132ARZMSOP  [SOP65P490X110-8N]  88.65,142.75 90 top
D12:C1  100n  [C0402]  86.11,133.86 180 bottom
D12:C2  10n  [C0402]  86.11,135.13 180 bottom
D12:C3  100n  [C0402]  89.28,134.49 0 bottom
D12:C4  10n  [C0402]  89.28,135.76 0 bottom
D12:C7  10n  [C0402]  86.74,130.05 270 bottom
D12:C31  4.7n  [C0603]  76.9,136.08 180 top
D12:C32  150p  [C0402]  81.66,134.49 90 top
D12:C33  27p  [C0402]  86.11,134.81 90 top
D12:C34  nc  [C0402]  92.46,135.13 0 top
D12:C35  10n  [C0402]  91.19,130.05 180 bottom
D12:C36  100n  [C0603]  76.9,133.86 0 top
D12:C41  4.7n  [C0603]  76.9,129.41 180 top
D12:C42  150p  [C0402]  81.66,131.32 270 top
D12:C43  27p  [C0402]  86.11,130.05 270 top
D12:C44  nc  [C0402]  92.46,128.78 0 top
D12:C45  10n  [C0402]  92.46,135.13 180 bottom
D12:C46  100n  [C0603]  76.9,131.64 0 top
D12:R1  1K  [R0402]  84.52,130.37 180 bottom
D12:R31  24.3E  [R0603]  79.76,135.45 270 top
D12:R32  24.3E  [R0603]  83.88,133.86 0 top
D12:R33  2K7  [R0603]  83.88,136.08 0 top
D12:R34  200E  [R0402]  92.46,136.4 0 top
D12:R35  1K4  [R0402]  94.68,135.45 270 top
D12:R36  10K  [R0402]  73.72,133.22 180 top
D12:R37  100K  [R0603]  74.04,135.45 270 top
D12:R38  NC  [R0402]  96.27,134.81 270 top
D12:R39  10E  [R0402]  91.19,131.32 0 bottom
D12:R41  24.3E  [R0603]  79.76,130.05 90 top
D12:R42  24.3E  [R0603]  83.88,131.64 0 top
D12:R43  2K7  [R0603]  83.88,129.41 0 top
D12:R44  200E  [R0402]  92.46,130.05 0 top
D12:R45  1K5  [R0402]  92.46,132.59 180 top
D12:R46  10K  [R0402]  73.72,131.95 0 top
D12:R47  100K  [R0603]  74.04,129.73 270 top
D12:R48  20K  [R0402]  95.95,129.73 270 top
D12:R49  10E  [R0402]  92.46,133.22 0 bottom
D12:R50  470E  [R0402]  74.04,129.73 90 bottom
D12:R51  nc  [R0402]  92.46,133.86 180 top
D12:R61  nc  [R0402]  92.46,131.32 180 top
D12:U1  AD8132ARZMSOP  [SOP65P490X110-8N]  88.65,132.59 90 top
D13:C1  100n  [C0402]  39.12,132.59 180 bottom
D13:C2  10n  [C0402]  39.12,133.86 180 bottom
D13:C3  100n  [C0402]  42.29,133.22 0 bottom
D13:C4  10n  [C0402]  42.29,134.49 0 bottom
D13:C7  10n  [C0402]  39.75,128.78 270 bottom
D13:C31  4.7n  [C0603]  29.91,134.81 180 top
D13:C32  150p  [C0402]  34.67,133.22 90 top
D13:C33  27p  [C0402]  39.12,133.54 90 top
D13:C34  nc  [C0402]  45.47,133.86 0 top
D13:C35  10n  [C0402]  44.2,128.78 180 bottom
D13:C36  100n  [C0603]  29.91,132.59 0 top
D13:C41  4.7n  [C0603]  29.91,128.14 180 top
D13:C42  150p  [C0402]  34.67,130.05 270 top
D13:C43  27p  [C0402]  39.12,128.78 270 top
D13:C44  nc  [C0402]  45.47,127.51 0 top
D13:C45  10n  [C0402]  45.47,133.86 180 bottom
D13:C46  100n  [C0603]  29.91,130.37 0 top
D13:R1  1K  [R0402]  37.53,129.1 180 bottom
D13:R31  24.3E  [R0603]  32.77,134.18 270 top
D13:R32  24.3E  [R0603]  36.89,132.59 0 top
D13:R33  2K7  [R0603]  36.89,134.81 0 top
D13:R34  200E  [R0402]  45.47,135.13 0 top
D13:R35  1K4  [R0402]  47.69,134.18 270 top
D13:R36  10K  [R0402]  26.73,131.95 180 top
D13:R37  100K  [R0603]  27.05,134.18 270 top
D13:R38  NC  [R0402]  49.28,133.54 270 top
D13:R39  10E  [R0402]  44.2,130.05 0 bottom
D13:R41  24.3E  [R0603]  32.77,128.78 90 top
D13:R42  24.3E  [R0603]  36.89,130.37 0 top
D13:R43  2K7  [R0603]  36.89,128.14 0 top
D13:R44  200E  [R0402]  45.47,128.78 0 top
D13:R45  1K5  [R0402]  45.47,131.32 180 top
D13:R46  10K  [R0402]  26.73,130.68 0 top
D13:R47  100K  [R0603]  27.05,128.46 270 top
D13:R48  20K  [R0402]  48.96,128.46 270 top
D13:R49  10E  [R0402]  45.47,131.95 0 bottom
D13:R50  470E  [R0402]  27.05,128.46 90 bottom
D13:R51  nc  [R0402]  45.47,132.59 180 top
D13:R61  nc  [R0402]  45.47,130.05 180 top
D13:U1  AD8132ARZMSOP  [SOP65P490X110-8N]  41.66,131.32 90 top
D14:C1  100n  [C0402]  86.11,118.62 180 bottom
D14:C2  10n  [C0402]  86.11,119.89 180 bottom
D14:C3  100n  [C0402]  89.28,119.25 0 bottom
D14:C4  10n  [C0402]  89.28,120.52 0 bottom
D14:C7  10n  [C0402]  86.74,114.81 270 bottom
D14:C31  4.7n  [C0603]  76.9,120.84 180 top
D14:C32  150p  [C0402]  81.66,119.25 90 top
D14:C33  27p  [C0402]  86.11,119.57 90 top
D14:C34  nc  [C0402]  92.46,119.89 0 top
D14:C35  10n  [C0402]  91.19,114.81 180 bottom
D14:C36  100n  [C0603]  76.9,118.62 0 top
D14:C41  4.7n  [C0603]  76.9,114.17 180 top
D14:C42  150p  [C0402]  81.66,116.08 270 top
D14:C43  27p  [C0402]  86.11,114.81 270 top
D14:C44  nc  [C0402]  92.46,113.54 0 top
D14:C45  10n  [C0402]  92.46,119.89 180 bottom
D14:C46  100n  [C0603]  76.9,116.4 0 top
D14:R1  1K  [R0402]  84.52,115.13 180 bottom
D14:R31  24.3E  [R0603]  79.76,120.21 270 top
D14:R32  24.3E  [R0603]  83.88,118.62 0 top
D14:R33  2K7  [R0603]  83.88,120.84 0 top
D14:R34  200E  [R0402]  92.46,121.16 0 top
D14:R35  1K4  [R0402]  94.68,120.21 270 top
D14:R36  10K  [R0402]  73.72,117.98 180 top
D14:R37  100K  [R0603]  74.04,120.21 270 top
D14:R38  NC  [R0402]  96.27,119.57 270 top
D14:R39  10E  [R0402]  91.19,116.08 0 bottom
D14:R41  24.3E  [R0603]  79.76,114.81 90 top
D14:R42  24.3E  [R0603]  83.88,116.4 0 top
D14:R43  2K7  [R0603]  83.88,114.17 0 top
D14:R44  200E  [R0402]  92.46,114.81 0 top
D14:R45  1K5  [R0402]  92.46,117.35 180 top
D14:R46  10K  [R0402]  73.72,116.71 0 top
D14:R47  100K  [R0603]  74.04,114.49 270 top
D14:R48  20K  [R0402]  95.95,114.49 270 top
D14:R49  10E  [R0402]  92.46,117.98 0 bottom
D14:R50  470E  [R0402]  74.04,114.49 90 bottom
D14:R51  nc  [R0402]  92.46,118.62 180 top
D14:R61  nc  [R0402]  92.46,116.08 180 top
D14:U1  AD8132ARZMSOP  [SOP65P490X110-8N]  88.65,117.35 90 top
D15:C1  100n  [C0402]  39.12,119.89 180 bottom
D15:C2  10n  [C0402]  39.12,121.16 180 bottom
D15:C3  100n  [C0402]  42.29,120.52 0 bottom
D15:C4  10n  [C0402]  42.29,121.79 0 bottom
D15:C7  10n  [C0402]  39.75,116.08 270 bottom
D15:C31  4.7n  [C0603]  29.91,122.11 180 top
D15:C32  150p  [C0402]  34.67,120.52 90 top
D15:C33  27p  [C0402]  39.12,120.84 90 top
D15:C34  nc  [C0402]  45.47,121.16 0 top
D15:C35  10n  [C0402]  44.2,116.08 180 bottom
D15:C36  100n  [C0603]  29.91,119.89 0 top
D15:C41  4.7n  [C0603]  29.91,115.44 180 top
D15:C42  150p  [C0402]  34.67,117.35 270 top
D15:C43  27p  [C0402]  39.12,116.08 270 top
D15:C44  nc  [C0402]  45.47,114.81 0 top
D15:C45  10n  [C0402]  45.47,121.16 180 bottom
D15:C46  100n  [C0603]  29.91,117.67 0 top
D15:R1  1K  [R0402]  37.53,116.4 180 bottom
D15:R31  24.3E  [R0603]  32.77,121.48 270 top
D15:R32  24.3E  [R0603]  36.89,119.89 0 top
D15:R33  2K7  [R0603]  36.89,122.11 0 top
D15:R34  200E  [R0402]  45.47,122.43 0 top
D15:R35  1K4  [R0402]  47.69,121.48 270 top
D15:R36  10K  [R0402]  26.73,119.25 180 top
D15:R37  100K  [R0603]  27.05,121.48 270 top
D15:R38  NC  [R0402]  49.28,120.84 270 top
D15:R39  10E  [R0402]  44.2,117.35 0 bottom
D15:R41  24.3E  [R0603]  32.77,116.08 90 top
D15:R42  24.3E  [R0603]  36.89,117.67 0 top
D15:R43  2K7  [R0603]  36.89,115.44 0 top
D15:R44  200E  [R0402]  45.47,116.08 0 top
D15:R45  1K5  [R0402]  45.47,118.62 180 top
D15:R46  10K  [R0402]  26.73,117.98 0 top
D15:R47  100K  [R0603]  27.05,115.76 270 top
D15:R48  20K  [R0402]  48.96,115.76 270 top
D15:R49  10E  [R0402]  45.47,119.25 0 bottom
D15:R50  470E  [R0402]  27.05,115.76 90 bottom
D15:R51  nc  [R0402]  45.47,119.89 180 top
D15:R61  nc  [R0402]  45.47,117.35 180 top
D15:U1  AD8132ARZMSOP  [SOP65P490X110-8N]  41.66,118.62 90 top
D16:C1  100n  [C0402]  39.12,103.38 180 bottom
D16:C2  10n  [C0402]  39.12,104.65 180 bottom
D16:C3  100n  [C0402]  42.29,104.01 0 bottom
D16:C4  10n  [C0402]  42.29,105.28 0 bottom
D16:C7  10n  [C0402]  39.75,99.57 270 bottom
D16:C31  4.7n  [C0603]  29.91,105.6 180 top
D16:C32  150p  [C0402]  34.67,104.01 90 top
D16:C33  27p  [C0402]  39.12,104.33 90 top
D16:C34  nc  [C0402]  45.47,104.65 0 top
D16:C35  10n  [C0402]  44.2,99.57 180 bottom
D16:C36  100n  [C0603]  29.91,103.38 0 top
D16:C41  4.7n  [C0603]  29.91,98.93 180 top
D16:C42  150p  [C0402]  34.67,100.84 270 top
D16:C43  27p  [C0402]  39.12,99.57 270 top
D16:C44  nc  [C0402]  45.47,98.3 0 top
D16:C45  10n  [C0402]  45.47,104.65 180 bottom
D16:C46  100n  [C0603]  29.91,101.16 0 top
D16:R1  1K  [R0402]  37.53,99.89 180 bottom
D16:R31  24.3E  [R0603]  32.77,104.97 270 top
D16:R32  24.3E  [R0603]  36.89,103.38 0 top
D16:R33  2K7  [R0603]  36.89,105.6 0 top
D16:R34  200E  [R0402]  45.47,105.92 0 top
D16:R35  1K4  [R0402]  47.69,104.97 270 top
D16:R36  10K  [R0402]  26.73,102.74 180 top
D16:R37  100K  [R0603]  27.05,104.97 270 top
D16:R38  NC  [R0402]  49.28,104.33 270 top
D16:R39  10E  [R0402]  44.2,100.84 0 bottom
D16:R41  24.3E  [R0603]  32.77,99.57 90 top
D16:R42  24.3E  [R0603]  36.89,101.16 0 top
D16:R43  2K7  [R0603]  36.89,98.93 0 top
D16:R44  200E  [R0402]  45.47,99.57 0 top
D16:R45  1K5  [R0402]  45.47,102.11 180 top
D16:R46  10K  [R0402]  26.73,101.47 0 top
D16:R47  100K  [R0603]  27.05,99.25 270 top
D16:R48  20K  [R0402]  48.96,99.25 270 top
D16:R49  10E  [R0402]  45.47,102.74 0 bottom
D16:R50  470E  [R0402]  27.05,99.25 90 bottom
D16:R51  nc  [R0402]  45.47,103.38 180 top
D16:R61  nc  [R0402]  45.47,100.84 180 top
D16:U1  AD8132ARZMSOP  [SOP65P490X110-8N]  41.66,102.11 90 top
D17:C1  100n  [C0402]  75.31,100.46 180 bottom
D17:C2  10n  [C0402]  75.31,101.73 180 bottom
D17:C3  100n  [C0402]  78.49,101.09 0 bottom
D17:C4  10n  [C0402]  78.49,102.36 0 bottom
D17:C7  10n  [C0402]  75.95,96.65 270 bottom
D17:C31  4.7n  [C0603]  66.1,102.68 180 top
D17:C32  150p  [C0402]  70.87,101.09 90 top
D17:C33  27p  [C0402]  75.31,101.41 90 top
D17:C34  nc  [C0402]  81.66,101.73 0 top
D17:C35  10n  [C0402]  80.39,96.65 180 bottom
D17:C36  100n  [C0603]  66.1,100.46 0 top
D17:C41  4.7n  [C0603]  66.1,96.01 180 top
D17:C42  150p  [C0402]  70.87,97.92 270 top
D17:C43  27p  [C0402]  75.31,96.65 270 top
D17:C44  nc  [C0402]  81.66,95.38 0 top
D17:C45  10n  [C0402]  81.66,101.73 180 bottom
D17:C46  100n  [C0603]  66.1,98.23 0 top
D17:R1  1K  [R0402]  73.72,96.96 180 bottom
D17:R31  24.3E  [R0603]  68.96,102.04 270 top
D17:R32  24.3E  [R0603]  73.09,100.46 0 top
D17:R33  2K7  [R0603]  73.09,102.68 0 top
D17:R34  200E  [R0402]  81.66,103 0 top
D17:R35  1K4  [R0402]  83.88,102.04 270 top
D17:R36  10K  [R0402]  62.93,99.82 180 top
D17:R37  100K  [R0603]  63.25,102.04 270 top
D17:R38  NC  [R0402]  85.47,101.41 270 top
D17:R39  10E  [R0402]  80.39,97.92 0 bottom
D17:R41  24.3E  [R0603]  68.96,96.65 90 top
D17:R42  24.3E  [R0603]  73.09,98.23 0 top
D17:R43  2K7  [R0603]  73.09,96.01 0 top
D17:R44  200E  [R0402]  81.66,96.65 0 top
D17:R45  1K5  [R0402]  81.66,99.19 180 top
D17:R46  10K  [R0402]  62.93,98.55 0 top
D17:R47  100K  [R0603]  63.25,96.33 270 top
D17:R48  20K  [R0402]  85.15,96.33 270 top
D17:R49  10E  [R0402]  81.66,99.82 0 bottom
D17:R50  470E  [R0402]  63.25,96.33 90 bottom
D17:R51  nc  [R0402]  81.66,100.46 180 top
D17:R61  nc  [R0402]  81.66,97.92 180 top
D17:U1  AD8132ARZMSOP  [SOP65P490X110-8N]  77.85,99.19 90 top
D18:C1  100n  [C0402]  39.12,92.2 180 bottom
D18:C2  10n  [C0402]  39.12,93.47 180 bottom
D18:C3  100n  [C0402]  42.29,92.84 0 bottom
D18:C4  10n  [C0402]  42.29,94.11 0 bottom
D18:C7  10n  [C0402]  39.75,88.39 270 bottom
D18:C31  4.7n  [C0603]  29.91,94.42 180 top
D18:C32  150p  [C0402]  34.67,92.84 90 top
D18:C33  27p  [C0402]  39.12,93.15 90 top
D18:C34  nc  [C0402]  45.47,93.47 0 top
D18:C35  10n  [C0402]  44.2,88.39 180 bottom
D18:C36  100n  [C0603]  29.91,92.2 0 top
D18:C41  4.7n  [C0603]  29.91,87.76 180 top
D18:C42  150p  [C0402]  34.67,89.66 270 top
D18:C43  27p  [C0402]  39.12,88.39 270 top
D18:C44  nc  [C0402]  45.47,87.12 0 top
D18:C45  10n  [C0402]  45.47,93.47 180 bottom
D18:C46  100n  [C0603]  29.91,89.98 0 top
D18:R1  1K  [R0402]  37.53,88.71 180 bottom
D18:R31  24.3E  [R0603]  32.77,93.79 270 top
D18:R32  24.3E  [R0603]  36.89,92.2 0 top
D18:R33  2K7  [R0603]  36.89,94.42 0 top
D18:R34  200E  [R0402]  45.47,94.74 0 top
D18:R35  1K4  [R0402]  47.69,93.79 270 top
D18:R36  10K  [R0402]  26.73,91.57 180 top
D18:R37  100K  [R0603]  27.05,93.79 270 top
D18:R38  NC  [R0402]  49.28,93.15 270 top
D18:R39  10E  [R0402]  44.2,89.66 0 bottom
D18:R41  24.3E  [R0603]  32.77,88.39 90 top
D18:R42  24.3E  [R0603]  36.89,89.98 0 top
D18:R43  2K7  [R0603]  36.89,87.76 0 top
D18:R44  200E  [R0402]  45.47,88.39 0 top
D18:R45  1K5  [R0402]  45.47,90.93 180 top
D18:R46  10K  [R0402]  26.73,90.3 0 top
D18:R47  100K  [R0603]  27.05,88.07 270 top
D18:R48  20K  [R0402]  48.96,88.07 270 top
D18:R49  10E  [R0402]  45.47,91.57 0 bottom
D18:R50  470E  [R0402]  27.05,88.07 90 bottom
D18:R51  nc  [R0402]  45.47,92.2 180 top
D18:R61  nc  [R0402]  45.47,89.66 180 top
D18:U1  AD8132ARZMSOP  [SOP65P490X110-8N]  41.66,90.93 90 top
D19:C1  100n  [C0402]  75.31,89.03 180 bottom
D19:C2  10n  [C0402]  75.31,90.3 180 bottom
D19:C3  100n  [C0402]  78.49,89.66 0 bottom
D19:C4  10n  [C0402]  78.49,90.93 0 bottom
D19:C7  10n  [C0402]  75.95,85.22 270 bottom
D19:C31  4.7n  [C0603]  66.1,91.25 180 top
D19:C32  150p  [C0402]  70.87,89.66 90 top
D19:C33  27p  [C0402]  75.31,89.98 90 top
D19:C34  nc  [C0402]  81.66,90.3 0 top
D19:C35  10n  [C0402]  80.39,85.22 180 bottom
D19:C36  100n  [C0603]  66.1,89.03 0 top
D19:C41  4.7n  [C0603]  66.1,84.58 180 top
D19:C42  150p  [C0402]  70.87,86.49 270 top
D19:C43  27p  [C0402]  75.31,85.22 270 top
D19:C44  nc  [C0402]  81.66,83.95 0 top
D19:C45  10n  [C0402]  81.66,90.3 180 bottom
D19:C46  100n  [C0603]  66.1,86.8 0 top
D19:R1  1K  [R0402]  73.72,85.53 180 bottom
D19:R31  24.3E  [R0603]  68.96,90.61 270 top
D19:R32  24.3E  [R0603]  73.09,89.03 0 top
D19:R33  2K7  [R0603]  73.09,91.25 0 top
D19:R34  200E  [R0402]  81.66,91.57 0 top
D19:R35  1K4  [R0402]  83.88,90.61 270 top
D19:R36  10K  [R0402]  62.93,88.39 180 top
D19:R37  100K  [R0603]  63.25,90.61 270 top
D19:R38  NC  [R0402]  85.47,89.98 270 top
D19:R39  10E  [R0402]  80.39,86.49 0 bottom
D19:R41  24.3E  [R0603]  68.96,85.22 90 top
D19:R42  24.3E  [R0603]  73.09,86.8 0 top
D19:R43  2K7  [R0603]  73.09,84.58 0 top
D19:R44  200E  [R0402]  81.66,85.22 0 top
D19:R45  1K5  [R0402]  81.66,87.76 180 top
D19:R46  10K  [R0402]  62.93,87.12 0 top
D19:R47  100K  [R0603]  63.25,84.9 270 top
D19:R48  20K  [R0402]  85.15,84.9 270 top
D19:R49  10E  [R0402]  81.66,88.39 0 bottom
D19:R50  470E  [R0402]  63.25,84.9 90 bottom
D19:R51  nc  [R0402]  81.66,89.03 180 top
D19:R61  nc  [R0402]  81.66,86.49 180 top
D19:U1  AD8132ARZMSOP  [SOP65P490X110-8N]  77.85,87.76 90 top
D20:C1  100n  [C0402]  40.39,76.71 180 bottom
D20:C2  10n  [C0402]  40.39,77.98 180 bottom
D20:C3  100n  [C0402]  43.56,77.34 0 bottom
D20:C4  10n  [C0402]  43.56,78.61 0 bottom
D20:C7  10n  [C0402]  41.02,72.9 270 bottom
D20:C31  4.7n  [C0603]  31.18,78.93 180 top
D20:C32  150p  [C0402]  35.94,77.34 90 top
D20:C33  27p  [C0402]  40.39,77.66 90 top
D20:C34  nc  [C0402]  46.74,77.98 0 top
D20:C35  10n  [C0402]  45.47,72.9 180 bottom
D20:C36  100n  [C0603]  31.18,76.71 0 top
D20:C41  4.7n  [C0603]  31.18,72.26 180 top
D20:C42  150p  [C0402]  35.94,74.17 270 top
D20:C43  27p  [C0402]  40.39,72.9 270 top
D20:C44  nc  [C0402]  46.74,71.63 0 top
D20:C45  10n  [C0402]  46.74,77.98 180 bottom
D20:C46  100n  [C0603]  31.18,74.49 0 top
D20:R1  1K  [R0402]  38.8,73.22 180 bottom
D20:R31  24.3E  [R0603]  34.04,78.3 270 top
D20:R32  24.3E  [R0603]  38.16,76.71 0 top
D20:R33  2K7  [R0603]  38.16,78.93 0 top
D20:R34  200E  [R0402]  46.74,79.25 0 top
D20:R35  1K4  [R0402]  48.96,78.3 270 top
D20:R36  10K  [R0402]  28,76.07 180 top
D20:R37  100K  [R0603]  28.32,78.3 270 top
D20:R38  NC  [R0402]  50.55,77.66 270 top
D20:R39  10E  [R0402]  45.47,74.17 0 bottom
D20:R41  24.3E  [R0603]  34.04,72.9 90 top
D20:R42  24.3E  [R0603]  38.16,74.49 0 top
D20:R43  2K7  [R0603]  38.16,72.26 0 top
D20:R44  200E  [R0402]  46.74,72.9 0 top
D20:R45  1K5  [R0402]  46.74,75.44 180 top
D20:R46  10K  [R0402]  28,74.8 0 top
D20:R47  100K  [R0603]  28.32,72.58 270 top
D20:R48  20K  [R0402]  50.23,72.58 270 top
D20:R49  10E  [R0402]  46.74,76.07 0 bottom
D20:R50  470E  [R0402]  28.32,72.58 90 bottom
D20:R51  nc  [R0402]  46.74,76.71 180 top
D20:R61  nc  [R0402]  46.74,74.17 180 top
D20:U1  AD8132ARZMSOP  [SOP65P490X110-8N]  42.93,75.44 90 top
D21:C1  100n  [C0402]  82.3,74.17 180 bottom
D21:C2  10n  [C0402]  82.3,75.44 180 bottom
D21:C3  100n  [C0402]  85.47,74.8 0 bottom
D21:C4  10n  [C0402]  85.47,76.07 0 bottom
D21:C7  10n  [C0402]  82.93,70.36 270 bottom
D21:C31  4.7n  [C0603]  73.09,76.39 180 top
D21:C32  150p  [C0402]  77.85,74.8 90 top
D21:C33  27p  [C0402]  82.3,75.12 90 top
D21:C34  nc  [C0402]  88.65,75.44 0 top
D21:C35  10n  [C0402]  87.38,70.36 180 bottom
D21:C36  100n  [C0603]  73.09,74.17 0 top
D21:C41  4.7n  [C0603]  73.09,69.72 180 top
D21:C42  150p  [C0402]  77.85,71.63 270 top
D21:C43  27p  [C0402]  82.3,70.36 270 top
D21:C44  nc  [C0402]  88.65,69.09 0 top
D21:C45  10n  [C0402]  88.65,75.44 180 bottom
D21:C46  100n  [C0603]  73.09,71.95 0 top
D21:R1  1K  [R0402]  80.71,70.68 180 bottom
D21:R31  24.3E  [R0603]  75.95,75.76 270 top
D21:R32  24.3E  [R0603]  80.07,74.17 0 top
D21:R33  2K7  [R0603]  80.07,76.39 0 top
D21:R34  200E  [R0402]  88.65,76.71 0 top
D21:R35  1K4  [R0402]  90.87,75.76 270 top
D21:R36  10K  [R0402]  69.91,73.53 180 top
D21:R37  100K  [R0603]  70.23,75.76 270 top
D21:R38  NC  [R0402]  92.46,75.12 270 top
D21:R39  10E  [R0402]  87.38,71.63 0 bottom
D21:R41  24.3E  [R0603]  75.95,70.36 90 top
D21:R42  24.3E  [R0603]  80.07,71.95 0 top
D21:R43  2K7  [R0603]  80.07,69.72 0 top
D21:R44  200E  [R0402]  88.65,70.36 0 top
D21:R45  1K5  [R0402]  88.65,72.9 180 top
D21:R46  10K  [R0402]  69.91,72.26 0 top
D21:R47  100K  [R0603]  70.23,70.04 270 top
D21:R48  20K  [R0402]  92.14,70.04 270 top
D21:R49  10E  [R0402]  88.65,73.53 0 bottom
D21:R50  470E  [R0402]  70.23,70.04 90 bottom
D21:R51  nc  [R0402]  88.65,74.17 180 top
D21:R61  nc  [R0402]  88.65,71.63 180 top
D21:U1  AD8132ARZMSOP  [SOP65P490X110-8N]  84.84,72.9 90 top
D22:C1  100n  [C0402]  39.12,65.28 180 bottom
D22:C2  10n  [C0402]  39.12,66.55 180 bottom
D22:C3  100n  [C0402]  42.29,65.91 0 bottom
D22:C4  10n  [C0402]  42.29,67.18 0 bottom
D22:C7  10n  [C0402]  39.75,61.47 270 bottom
D22:C31  4.7n  [C0603]  29.91,67.5 180 top
D22:C32  150p  [C0402]  34.67,65.91 90 top
D22:C33  27p  [C0402]  39.12,66.23 90 top
D22:C34  nc  [C0402]  45.47,66.55 0 top
D22:C35  10n  [C0402]  44.2,61.47 180 bottom
D22:C36  100n  [C0603]  29.91,65.28 0 top
D22:C41  4.7n  [C0603]  29.91,60.83 180 top
D22:C42  150p  [C0402]  34.67,62.74 270 top
D22:C43  27p  [C0402]  39.12,61.47 270 top
D22:C44  nc  [C0402]  45.47,60.2 0 top
D22:C45  10n  [C0402]  45.47,66.55 180 bottom
D22:C46  100n  [C0603]  29.91,63.06 0 top
D22:R1  1K  [R0402]  37.53,61.79 180 bottom
D22:R31  24.3E  [R0603]  32.77,66.87 270 top
D22:R32  24.3E  [R0603]  36.89,65.28 0 top
D22:R33  2K7  [R0603]  36.89,67.5 0 top
D22:R34  200E  [R0402]  45.47,67.82 0 top
D22:R35  1K4  [R0402]  47.69,66.87 270 top
D22:R36  10K  [R0402]  26.73,64.64 180 top
D22:R37  100K  [R0603]  27.05,66.87 270 top
D22:R38  NC  [R0402]  49.28,66.23 270 top
D22:R39  10E  [R0402]  44.2,62.74 0 bottom
D22:R41  24.3E  [R0603]  32.77,61.47 90 top
D22:R42  24.3E  [R0603]  36.89,63.06 0 top
D22:R43  2K7  [R0603]  36.89,60.83 0 top
D22:R44  200E  [R0402]  45.47,61.47 0 top
D22:R45  1K5  [R0402]  45.47,64.01 180 top
D22:R46  10K  [R0402]  26.73,63.37 0 top
D22:R47  100K  [R0603]  27.05,61.15 270 top
D22:R48  20K  [R0402]  48.96,61.15 270 top
D22:R49  10E  [R0402]  45.47,64.64 0 bottom
D22:R50  470E  [R0402]  27.05,61.15 90 bottom
D22:R51  nc  [R0402]  45.47,65.28 180 top
D22:R61  nc  [R0402]  45.47,62.74 180 top
D22:U1  AD8132ARZMSOP  [SOP65P490X110-8N]  41.66,64.01 90 top
D23:C1  100n  [C0402]  86.11,62.74 180 bottom
D23:C2  10n  [C0402]  86.11,64.01 180 bottom
D23:C3  100n  [C0402]  89.28,63.37 0 bottom
D23:C4  10n  [C0402]  89.28,64.64 0 bottom
D23:C7  10n  [C0402]  86.74,58.93 270 bottom
D23:C31  4.7n  [C0603]  76.9,64.96 180 top
D23:C32  150p  [C0402]  81.66,63.37 90 top
D23:C33  27p  [C0402]  86.11,63.69 90 top
D23:C34  nc  [C0402]  92.46,64.01 0 top
D23:C35  10n  [C0402]  91.19,58.93 180 bottom
D23:C36  100n  [C0603]  76.9,62.74 0 top
D23:C41  4.7n  [C0603]  76.9,58.29 180 top
D23:C42  150p  [C0402]  81.66,60.2 270 top
D23:C43  27p  [C0402]  86.11,58.93 270 top
D23:C44  nc  [C0402]  92.46,57.66 0 top
D23:C45  10n  [C0402]  92.46,64.01 180 bottom
D23:C46  100n  [C0603]  76.9,60.52 0 top
D23:R1  1K  [R0402]  84.52,59.25 180 bottom
D23:R31  24.3E  [R0603]  79.76,64.33 270 top
D23:R32  24.3E  [R0603]  83.88,62.74 0 top
D23:R33  2K7  [R0603]  83.88,64.96 0 top
D23:R34  200E  [R0402]  92.46,65.28 0 top
D23:R35  1K4  [R0402]  94.68,64.33 270 top
D23:R36  10K  [R0402]  73.72,62.1 180 top
D23:R37  100K  [R0603]  74.04,64.33 270 top
D23:R38  NC  [R0402]  96.27,63.69 270 top
D23:R39  10E  [R0402]  91.19,60.2 0 bottom
D23:R41  24.3E  [R0603]  79.76,58.93 90 top
D23:R42  24.3E  [R0603]  83.88,60.52 0 top
D23:R43  2K7  [R0603]  83.88,58.29 0 top
D23:R44  200E  [R0402]  92.46,58.93 0 top
D23:R45  1K5  [R0402]  92.46,61.47 180 top
D23:R46  10K  [R0402]  73.72,60.83 0 top
D23:R47  100K  [R0603]  74.04,58.61 270 top
D23:R48  20K  [R0402]  95.95,58.61 270 top
D23:R49  10E  [R0402]  92.46,62.1 0 bottom
D23:R50  470E  [R0402]  74.04,58.61 90 bottom
D23:R51  nc  [R0402]  92.46,62.74 180 top
D23:R61  nc  [R0402]  92.46,60.2 180 top
D23:U1  AD8132ARZMSOP  [SOP65P490X110-8N]  88.65,61.47 90 top
D24:C1  100n  [C0402]  39.12,50.04 180 bottom
D24:C2  10n  [C0402]  39.12,51.31 180 bottom
D24:C3  100n  [C0402]  42.29,50.67 0 bottom
D24:C4  10n  [C0402]  42.29,51.94 0 bottom
D24:C7  10n  [C0402]  39.75,46.23 270 bottom
D24:C31  4.7n  [C0603]  29.91,52.26 180 top
D24:C32  150p  [C0402]  34.67,50.67 90 top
